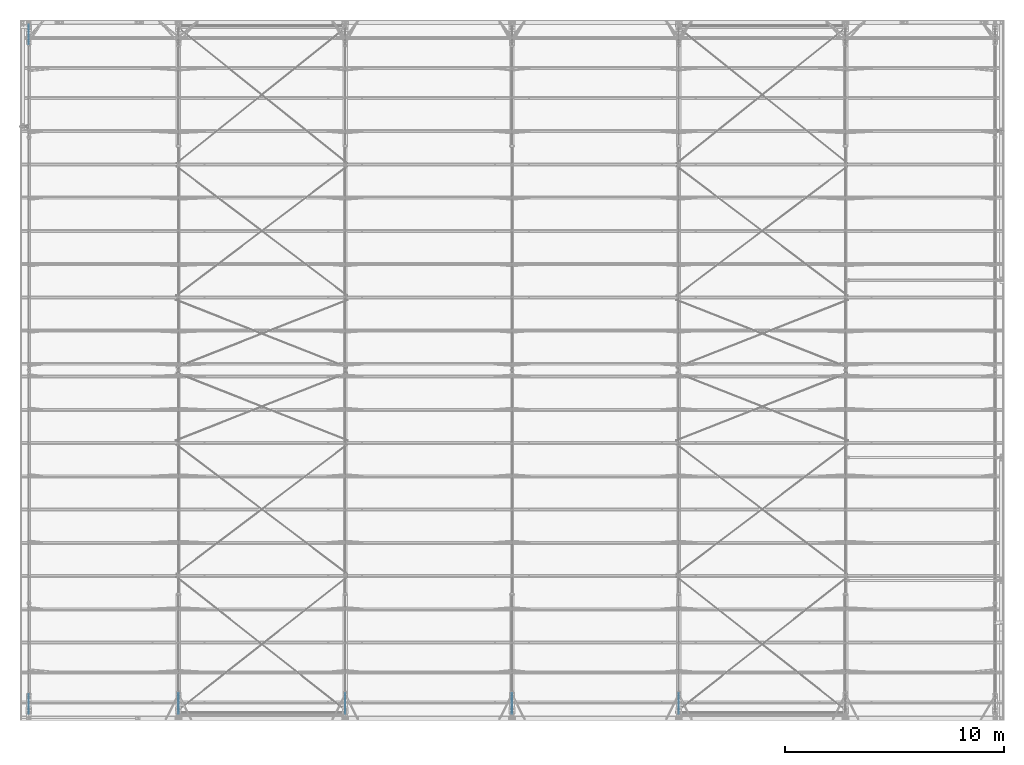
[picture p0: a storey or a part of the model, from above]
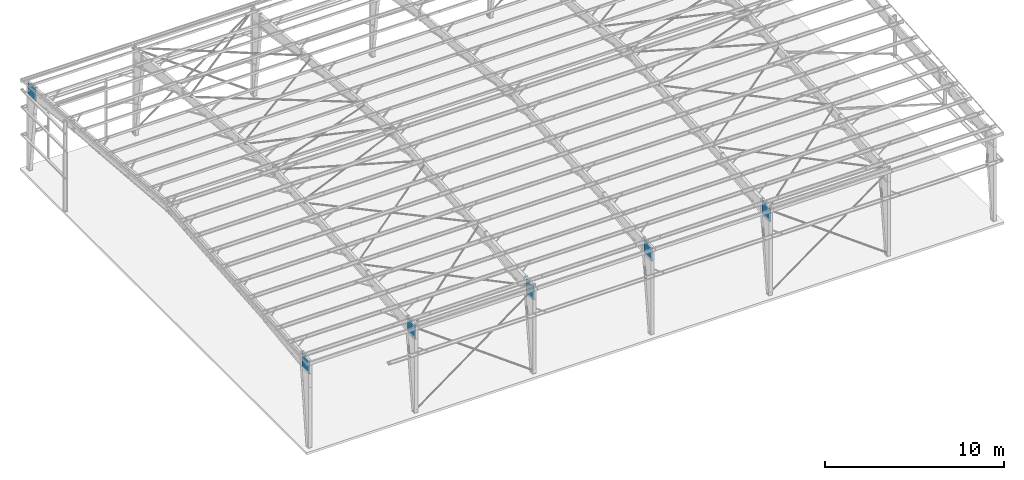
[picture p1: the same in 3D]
Properties of the parts of a building model (IFC2X3), part 1 of 2

# File
Description: ViewDefinition[CoordinationView_V1.0]
File name: IFC_Model.ifc
Time: 2022-11-29T19:15:44
Author: BG\Bryan.Morelli
Organization: Structural Designer
Written by: IFC Database Version:Work
Made in: Tekla Structures 2016i Service Pack 7, IFC Export Version: 4.0.0.0 Feb 5 2018

# IfcSite, Undefined
RefElevation: 0 mm

# IfcBuildingStorey, Undefined
In: Undefined
Elevation: 0 mm

# IfcBeam: 3/4_HEAVY_HEX_NUT (48)
In: Undefined
Description: 3/4_HEAVY_HEX_NUT; Material: STEEL/55
Tekla Common - Phase: 1; Class: 6
Tekla Quantity - Weight: 0.1 kg; Volume: 0 m3; Gross footprint area: 0 m2; Area per tons: 54.2 m2; Net surface area: 0 m2; Height: 31.6 mm; Width: 36.5 mm
Pset_BeamCommon - LoadBearing: yes; Reference: BH-80
Name | Bottom elevation | Top elevation | Length (mm)
5 x 3/4 H HEX NUT A563 | 20'-11"1/16 | 21'-0"3/8 | 19.1
6 x 3/4 H HEX NUT A563 | 20'-10"3/8 | 20'-11"11/16 | 19.1
7 x 3/4 H HEX NUT A563 | 22'-6"11/16 | 22'-7"15/16 | 19.1
7 x 3/4 H HEX NUT A563 | 23'-5"1/16 | 23'-6"5/16 | 19.1
3/4 H HEX NUT A563 | 22'-6"11/16 | 22'-7"15/16 | 19
3/4 H HEX NUT A563 | 23'-5"1/16 | 23'-6"5/16 | 19
5 x 3/4 H HEX NUT A563 | 22'-6"1/4 | 22'-7"1/2 | 19.1
3 x 3/4 H HEX NUT A563 | 22'-6"1/4 | 22'-7"1/2 | 19
3 x 3/4 H HEX NUT A563 | 20'-11"1/16 | 21'-0"3/8 | 19
4 x 3/4 H HEX NUT A563 | 19'-2"1/8 | 19'-3"3/8 | 19.1
2 x 3/4 H HEX NUT A563 | 20'-10"7/16 | 20'-11"11/16 | 19.1
4 x 3/4 H HEX NUT A563 | 19'-2"7/16 | 19'-3"11/16 | 19.1

# IfcBeam: 3/4_WASHER (48)
In: Undefined
Description: 3/4_WASHER; Material: STEEL/55
Tekla Common - Phase: 1; Class: 6
Tekla Quantity - Weight: 0 kg; Volume: 0 m3; Gross footprint area: 0 m2; Area per tons: 84.9 m2; Net surface area: 0 m2; Height: 36.4 mm; Width: 37.3 mm; Length: 4.8 mm
Pset_BeamCommon - LoadBearing: yes; Reference: BH-81
Name | Bottom elevation | Top elevation
8 x 3/4 WASHER F844 | 20'-11" | 21'-0"7/16
4 x 3/4 WASHER F844 | 20'-10"1/4 | 20'-11"3/4
4 x 3/4 WASHER F844 | 20'-10"5/16 | 20'-11"3/4
8 x 3/4 WASHER F844 | 22'-6"5/8 | 22'-8"1/16
8 x 3/4 WASHER F844 | 23'-4"15/16 | 23'-6"3/8
8 x 3/4 WASHER F844 | 22'-6"1/8 | 22'-7"9/16
4 x 3/4 WASHER F844 | 19'-2"1/16 | 19'-3"1/2
4 x 3/4 WASHER F844 | 19'-2"3/8 | 19'-3"13/16

# IfcBeam: 8C16 (4)
In: Undefined
Description: 8C16; Material: STEEL/55
Tekla Common - Finish: GZ; Phase: 1; Class: 12
Tekla Quantity - Volume: 0 m3; Area per tons: 171.1 m2; Height: 203.2 mm; Width: 63.5 mm
Pset_BeamCommon - LoadBearing: yes
Name | Bottom elevation | Top elevation | Weight (kg) | Gross footprint area (m2) | Net surface area (m2) | Length (mm) | Reference
2 x Jamb | 0" | 13'-4"1/2 | 17.4 | 0 | 2.9 | 4076.7 | C-12
2 x Header | 12'-0" | 12'-2"1/2 | 15.6 | 0.2 | 2.7 | 3657.6 | C-13

# IfcBeam: 8Z12 (6)
In: Undefined
Description: 8Z12; Material: STEEL/55
Tekla Common - Finish: GZ; Phase: 1; Class: 7
Tekla Quantity - Volume: 0 m3; Gross footprint area: 0 m2; Area per tons: 103.8 m2; Height: 203.2 mm; Width: 151.5 mm
Pset_BeamCommon - LoadBearing: yes
Name | Bottom elevation | Top elevation | Weight (kg) | Net surface area (m2) | Length (mm) | Reference
4 x Purlin | 19'-4"13/16 | 20'-1"3/16 | 54.9 | 5.7 | 7797.8 | Z-22
Girt | 13'-5" | 13'-11" | 57.1 | 6 | 8115.3 | Z-3
Girt | 13'-5" | 13'-11" | 57.1 | 6 | 8115.3 | Z-2

# IfcBeam: 8Z13 (46)
In: Undefined
Description: 8Z13; Material: STEEL/55
Tekla Common - Finish: GZ; Phase: 1; Class: 9
Tekla Quantity - Volume: 0 m3; Gross footprint area: 0 m2; Area per tons: 115.3 m2; Height: 203.2 mm; Width: 151.5 mm
Pset_BeamCommon - LoadBearing: yes
Name | Bottom elevation | Top elevation | Weight (kg) | Net surface area (m2) | Length (mm) | Reference
2 x Purlin | 19'-6"1/2 | 20'-2"7/8 | 53.5 | 6.2 | 8432.8 | Z-24
Purlin | 19'-11" | 20'-7"3/8 | 53.5 | 6.2 | 8432.8 | Z-28
2 x Purlin | 20'-3"7/16 | 20'-11"7/8 | 53.5 | 6.2 | 8432.8 | Z-24
2 x Purlin | 20'-8"7/16 | 21'-4"13/16 | 53.5 | 6.2 | 8432.8 | Z-24
2 x Purlin | 21'-1"7/16 | 21'-9"13/16 | 53.5 | 6.2 | 8432.8 | Z-24
2 x Purlin | 21'-6"7/16 | 22'-2"13/16 | 53.5 | 6.2 | 8432.8 | Z-24
2 x Purlin | 21'-11"3/8 | 22'-7"3/4 | 53.5 | 6.2 | 8432.8 | Z-24
2 x Purlin | 22'-4"3/8 | 23'-0"3/4 | 53.5 | 6.2 | 8432.8 | Z-24
2 x Purlin | 22'-9"3/8 | 23'-5"3/4 | 53.5 | 6.2 | 8432.8 | Z-24
2 x Purlin | 23'-2"5/16 | 23'-10"3/4 | 53.5 | 6.2 | 8432.8 | Z-24
2 x Purlin | 23'-7"5/16 | 24'-3"11/16 | 53.5 | 6.2 | 8432.8 | Z-24
2 x Purlin | 19'-6"1/2 | 20'-2"7/8 | 53.5 | 6.2 | 8432.8 | Z-23
Purlin | 19'-11" | 20'-7"3/8 | 53.5 | 6.2 | 8432.8 | Z-27
2 x Purlin | 20'-3"7/16 | 20'-11"7/8 | 53.5 | 6.2 | 8432.8 | Z-23
2 x Purlin | 20'-8"7/16 | 21'-4"13/16 | 53.5 | 6.2 | 8432.8 | Z-23
2 x Purlin | 21'-1"7/16 | 21'-9"13/16 | 53.5 | 6.2 | 8432.8 | Z-23
2 x Purlin | 21'-6"7/16 | 22'-2"13/16 | 53.5 | 6.2 | 8432.8 | Z-23
2 x Purlin | 21'-11"3/8 | 22'-7"3/4 | 53.5 | 6.2 | 8432.8 | Z-23
2 x Purlin | 22'-4"3/8 | 23'-0"3/4 | 53.5 | 6.2 | 8432.8 | Z-23
2 x Purlin | 22'-9"3/8 | 23'-5"3/4 | 53.5 | 6.2 | 8432.8 | Z-23
2 x Purlin | 23'-2"5/16 | 23'-10"3/4 | 53.5 | 6.2 | 8432.8 | Z-23
2 x Purlin | 23'-7"5/16 | 24'-3"11/16 | 53.5 | 6.2 | 8432.8 | Z-23
Purlin | 19'-11" | 20'-7"3/8 | 53.5 | 6.2 | 8432.8 | Z-26
Purlin | 19'-11" | 20'-7"3/8 | 53.5 | 6.2 | 8432.8 | Z-25
Girt | 13'-5" | 13'-11" | 42 | 4.9 | 6629.4 | Z-36
Girt | 13'-5" | 13'-11" | 39.9 | 4.6 | 6286.5 | Z-12

# IfcBeam: 8Z15 (96)
In: Undefined
Description: 8Z15; Material: STEEL/55
Tekla Common - Finish: GZ; Phase: 1; Class: 11
Tekla Quantity - Volume: 0 m3; Gross footprint area: 0 m2; Height: 203.2 mm; Width: 151.5 mm
Pset_BeamCommon - LoadBearing: yes
Name | Bottom elevation | Top elevation | Weight (kg) | Area per tons (m2) | Net surface area (m2) | Length (mm) | Reference
Girt | 7'-3" | 7'-9" | 22.7 | 151.6 | 3.4 | 4762.5 | Z-10
Girt | 7'-3" | 7'-9" | 23.6 | 151.7 | 3.6 | 4965.7 | Z-9
2 x Purlin | 19'-6"1/2 | 20'-2"7/8 | 45.8 | 153.5 | 7 | 9626.6 | Z-21
2 x Purlin | 19'-11" | 20'-7"3/8 | 45.8 | 153.5 | 7 | 9626.6 | Z-21
2 x Purlin | 20'-3"7/16 | 20'-11"7/8 | 45.8 | 153.5 | 7 | 9626.6 | Z-21
2 x Purlin | 20'-8"7/16 | 21'-4"13/16 | 45.8 | 153.5 | 7 | 9626.6 | Z-21
2 x Purlin | 21'-1"7/16 | 21'-9"13/16 | 45.8 | 153.5 | 7 | 9626.6 | Z-21
2 x Purlin | 21'-6"7/16 | 22'-2"13/16 | 45.8 | 153.5 | 7 | 9626.6 | Z-21
2 x Purlin | 21'-11"3/8 | 22'-7"3/4 | 45.8 | 153.5 | 7 | 9626.6 | Z-21
2 x Purlin | 22'-4"3/8 | 23'-0"3/4 | 45.8 | 153.5 | 7 | 9626.6 | Z-21
2 x Purlin | 22'-9"3/8 | 23'-5"3/4 | 45.8 | 153.5 | 7 | 9626.6 | Z-21
2 x Purlin | 23'-2"5/16 | 23'-10"3/4 | 45.8 | 153.5 | 7 | 9626.6 | Z-21
2 x Purlin | 23'-7"5/16 | 24'-3"11/16 | 45.8 | 153.5 | 7 | 9626.6 | Z-21
4 x Purlin | 19'-6"1/2 | 20'-2"7/8 | 43.9 | 153.5 | 6.7 | 9220.2 | Z-20
4 x Purlin | 19'-11" | 20'-7"3/8 | 43.9 | 153.5 | 6.7 | 9220.2 | Z-20
4 x Purlin | 20'-3"7/16 | 20'-11"7/8 | 43.9 | 153.5 | 6.7 | 9220.2 | Z-20
4 x Purlin | 20'-8"7/16 | 21'-4"13/16 | 43.9 | 153.5 | 6.7 | 9220.2 | Z-20
4 x Purlin | 21'-1"7/16 | 21'-9"13/16 | 43.9 | 153.5 | 6.7 | 9220.2 | Z-20
4 x Purlin | 21'-6"7/16 | 22'-2"13/16 | 43.9 | 153.5 | 6.7 | 9220.2 | Z-20
4 x Purlin | 21'-11"3/8 | 22'-7"3/4 | 43.9 | 153.5 | 6.7 | 9220.2 | Z-20
4 x Purlin | 22'-4"3/8 | 23'-0"3/4 | 43.9 | 153.5 | 6.7 | 9220.2 | Z-20
4 x Purlin | 22'-9"3/8 | 23'-5"3/4 | 43.9 | 153.5 | 6.7 | 9220.2 | Z-20
4 x Purlin | 23'-2"5/16 | 23'-10"3/4 | 43.9 | 153.5 | 6.7 | 9220.2 | Z-20
4 x Purlin | 23'-7"5/16 | 24'-3"11/16 | 43.9 | 153.5 | 6.7 | 9220.2 | Z-20
2 x Purlin | 19'-6"1/2 | 20'-2"7/8 | 45.8 | 153.5 | 7 | 9626.6 | Z-19
2 x Purlin | 19'-11" | 20'-7"3/8 | 45.8 | 153.5 | 7 | 9626.6 | Z-19
2 x Purlin | 20'-3"7/16 | 20'-11"7/8 | 45.8 | 153.5 | 7 | 9626.6 | Z-19
2 x Purlin | 20'-8"7/16 | 21'-4"13/16 | 45.8 | 153.5 | 7 | 9626.6 | Z-19
2 x Purlin | 21'-1"7/16 | 21'-9"13/16 | 45.8 | 153.5 | 7 | 9626.6 | Z-19
2 x Purlin | 21'-6"7/16 | 22'-2"13/16 | 45.8 | 153.5 | 7 | 9626.6 | Z-19
2 x Purlin | 21'-11"3/8 | 22'-7"3/4 | 45.8 | 153.5 | 7 | 9626.6 | Z-19
2 x Purlin | 22'-4"3/8 | 23'-0"3/4 | 45.8 | 153.5 | 7 | 9626.6 | Z-19
2 x Purlin | 22'-9"3/8 | 23'-5"3/4 | 45.8 | 153.5 | 7 | 9626.6 | Z-19
2 x Purlin | 23'-2"5/16 | 23'-10"3/4 | 45.8 | 153.5 | 7 | 9626.6 | Z-19
2 x Purlin | 23'-7"5/16 | 24'-3"11/16 | 45.8 | 153.5 | 7 | 9626.6 | Z-19
Girt | 17'-3" | 17'-9" | 22.7 | 153.5 | 3.4 | 4775.2 | Z-17
Girt | 13'-5" | 13'-11" | 22.7 | 151.6 | 3.4 | 4762.5 | Z-10
Girt | 13'-5" | 13'-11" | 23.6 | 151.7 | 3.6 | 4965.7 | Z-9
Girt | 13'-5" | 13'-11" | 25.9 | 153.5 | 4 | 5435.6 | Z-15
Girt | 13'-5" | 13'-11" | 43.4 | 153.5 | 6.7 | 9118.6 | Z-34
Girt | 13'-5" | 13'-11" | 43.4 | 153.5 | 6.7 | 9118.6 | Z-33

# IfcBeam: 8Z16 (19)
In: Undefined
Description: 8Z16; Material: STEEL/55
Tekla Common - Finish: GZ; Phase: 1; Class: 12
Tekla Quantity - Volume: 0 m3; Gross footprint area: 0 m2; Height: 203.2 mm; Width: 151.5 mm
Pset_BeamCommon - LoadBearing: yes
Name | Bottom elevation | Top elevation | Weight (kg) | Area per tons (m2) | Net surface area (m2) | Length (mm) | Reference
Girt | 7'-3" | 7'-9" | 7.2 | 171.4 | 1.2 | 1676.4 | Z-30
Girt | 7'-3" | 7'-9" | 14.9 | 171.1 | 2.5 | 3479.8 | Z-32
Girt | 19'-9" | 20'-3" | 28.3 | 171.1 | 4.9 | 6629.4 | Z-29
Girt | 19'-9" | 20'-3" | 23.2 | 171.1 | 4 | 5435.6 | Z-18
Girt | 19'-9" | 20'-3" | 9.5 | 171.4 | 1.6 | 2235.2 | Z-14
Girt | 13'-5" | 13'-11" | 33.4 | 171.1 | 5.7 | 7810.5 | Z-8
3 x Girt | 13'-5" | 13'-11" | 37.6 | 171.1 | 6.4 | 8813.8 | Z-31
Girt | 13'-5" | 13'-11" | 35 | 171.1 | 6 | 8204.2 | Z-7
Girt | 13'-5" | 13'-11" | 8.2 | 171.4 | 1.4 | 1930.4 | Z-6
Girt | 7'-3" | 7'-9" | 11.1 | 171.4 | 1.9 | 2603.5 | Z-5
Girt | 7'-3" | 7'-9" | 38.9 | 171.1 | 6.7 | 9118.6 | Z-16
2 x Girt | 13'-5" | 13'-11" | 37.6 | 171.1 | 6.4 | 8813.8 | Z-13
2 x Girt | 7'-3" | 7'-9" | 37.6 | 171.1 | 6.4 | 8813.8 | Z-13
Girt | 7'-3" | 7'-9" | 38.9 | 171.1 | 6.7 | 9118.6 | Z-1
Girt | 7'-3" | 7'-9" | 3.4 | 171.8 | 0.6 | 800.1 | Z-4

# IfcBeam: ESEIGHT1" (12)
In: Undefined
Description: ESEIGHT1"; Material: STEEL/55
Tekla Common - Finish: GZ; Bottom elevation: 19'-4"; Top elevation: 20'-0"5/16; Phase: 1; Class: 1
Tekla Quantity - Volume: 0 m3; Gross footprint area: 0 m2; Area per tons: 160.9 m2; Height: 212 mm; Width: 204.1 mm
Pset_BeamCommon - LoadBearing: yes
Name | Weight (kg) | Net surface area (m2) | Length (mm) | Reference
2 x Eave Strut | 55.4 | 8.9 | 7213.6 | GE8-2
8 x Eave Strut | 58.3 | 9.4 | 7594.6 | GE8-3
2 x Eave Strut | 55.4 | 8.9 | 7213.6 | GE8-1

# IfcBeam: FB- (35)
In: Undefined
Description: FB-; Material: STEEL/55
Tekla Common - Phase: 1; Class: 2
Tekla Quantity - Volume: 0 m3; Height: 50.8 mm; Width: 50.8 mm
Pset_BeamCommon - LoadBearing: yes
Name | Bottom elevation | Top elevation | Weight (kg) | Gross footprint area (m2) | Area per tons (m2) | Net surface area (m2) | Length (mm) | Reference
4 x 2X2 FLANGE BRACE X 48 | 7'-6" | 7'-8" | 1.4 | 0 | 163 | 0.2 | 1125.8 | FB-48
2 x 2X2 FLANGE BRACE X 36 | 7'-6"1/16 | 7'-8"1/16 | 1.2 | 0 | 163.1 | 0.2 | 934.6 | FB-36 | Tekla Common - Finish: RP
2X2 FLANGE BRACE X 60 | 13'-5"15/16 | 13'-7"15/16 | 1.4 | 0.1 | 163 | 0.2 | 1196.6 | FB-60 | Tekla Common - Finish: GZ
10 x 2X2 FLANGE BRACE X 60 | 13'-6" | 13'-8" | 1.4 | 0.1 | 163 | 0.2 | 1202.5 | FB-60 | Tekla Common - Finish: GZ
4 x 2X2 FLANGE BRACE X 60 | 13'-8" | 13'-10" | 1.6 | 0 | 163 | 0.3 | 1298.3 | FB-60
6 x 2X2 FLANGE BRACE X 48 | 7'-6" | 7'-8" | 1.1 | 0 | 163.1 | 0.2 | 912.7 | FB-48
6 x 2X2 FLANGE BRACE X 60 | 13'-8" | 13'-10" | 1.4 | 0 | 163 | 0.2 | 1120.2 | FB-60
2 x 2X2 FLANGE BRACE X 48 | 13'-8"1/16 | 13'-10"1/16 | 1.4 | 0 | 163 | 0.2 | 1115.7 | FB-48 | Tekla Common - Finish: RP

# IfcBeam: FL1/4"X5" (4)
In: Undefined
Description: FL1/4"X5"; Material: STEEL/55
Tekla Common - Finish: GP; Phase: 1; Class: 1
Tekla Quantity - Weight: 2.9 kg; Volume: 0 m3; Gross footprint area: 0 m2; Area per tons: 42.7 m2; Net surface area: 0.1 m2; Height: 127 mm; Width: 6.4 mm
Pset_BeamCommon - LoadBearing: yes; Reference: AC-151
Name | Bottom elevation | Top elevation | Length (mm)
Special Clip | 20'-0"5/8 | 20'-5"5/8 | 450.9
Special Clip | 20'-0"5/8 | 20'-5"5/8 | 450.8
Special Clip | 19'-11"15/16 | 20'-4"15/16 | 450.9
Special Clip | 19'-11"15/16 | 20'-4"15/16 | 450.8

# IfcBeam: FL1/4"X6" (22)
In: Undefined
Description: FL1/4"X6"; Material: STEEL/55
Tekla Common - Finish: GP; Phase: 1; Class: 2
Tekla Quantity - Volume: 0 m3; Gross footprint area: 0 m2; Net surface area: 0.1 m2; Height: 152.4 mm; Width: 6.4 mm
Pset_BeamCommon - LoadBearing: yes
Name | Bottom elevation | Top elevation | Weight (kg) | Area per tons (m2) | Length (mm) | Reference
12 x ANTI-ROLL CL 8 OR 9.5 | 23'-7"1/2 | 24'-3"1/4 | 2.5 | 42.6 | 323.8 | C-3
6 x 8 SECONDARY BYPASS | 13'-5" | 13'-8" | 2.7 | 42.5 | 342.9 | PX-100
2 x ANTI-ROLL CL 8 OR 9.5 | 23'-7"1/2 | 24'-3"1/4 | 2.5 | 42.6 | 323.8 | C-4
SPECIAL CLIP | 17'-6"1/16 | 17'-9"1/16 | 3.4 | 42.5 | 440.6 | AC-150
SPECIAL CLIP | 20'-0"1/16 | 20'-3"1/16 | 3.4 | 42.5 | 440.6 | AC-150

# IfcBeam: FL3/16"X5" (32)
In: Undefined
Description: FL3/16"X5"; Material: STEEL/55
Pset_BeamCommon - LoadBearing: yes; Reference: AC-01R
Tekla Common - Phase: 1; Class: 2
Tekla Quantity - Weight: 1.2 kg; Volume: 0 m3; Gross footprint area: 0 m2; Net surface area: 0.1 m2; Height: 127 mm; Width: 4.8 mm
Name | Finish | Bottom elevation | Top elevation | Area per tons (m2) | Length (mm)
5 x UNIVERSAL AC-1 CLIP | GZ | 7'-6" | 7'-8"3/4 | 56.5 | 244.5
UNIVERSAL AC-1 CLIP | GZ | 7'-6" | 7'-9" | 56.5 | 250.8
10 x UNIVERSAL AC-1 CLIP | GZ | 21'-1"5/8 | 21'-8"7/8 | 56.6 | 244.5
UNIVERSAL AC-1 CLIP | RP | 7'-6" | 7'-9" | 56.5 | 250.8
2 x UNIVERSAL AC-1 CLIP | GZ | 13'-8" | 13'-11" | 56.5 | 250.8
5 x UNIVERSAL AC-1 CLIP | GZ | 13'-8" | 13'-10"3/4 | 56.5 | 244.5
8 x UNIVERSAL AC-1 CLIP | GZ | 19'-5" | 20'-0"1/4 | 56.6 | 244.5

# IfcBeam: FLDPL2"X2"X1/16"X90" (7)
In: Undefined
Description: FLDPL2"X2"X1/16"X90"; Material: STEEL/55
Tekla Common - Finish: GZ; Phase: 1; Class: 9
Tekla Quantity - Weight: 0.3 kg; Volume: 0 m3; Gross footprint area: 0 m2; Area per tons: 164.3 m2; Net surface area: 0 m2; Height: 50.8 mm; Width: 50.8 mm; Length: 203.2 mm
Pset_BeamCommon - LoadBearing: yes; Reference: WA-8
Name | Bottom elevation | Top elevation
2 x WINDOW FRAME ANGLE | 7'-6"3/16 | 7'-8"3/16
3 x WINDOW FRAME ANGLE | 13'-8"3/16 | 13'-10"3/16
WINDOW FRAME ANGLE | 17'-6"3/16 | 17'-8"3/16
WINDOW FRAME ANGLE | 17'-6"1/16 | 17'-8"1/16

# IfcBeam: HSS4X4X1/4, PIPE
In: Undefined
Description: HSS4X4X1/4; Material: STEEL/55
Tekla Common - Finish: GP; Bottom elevation: 13'-10"11/16; Top elevation: 20'-10"3/16; Phase: 1; Class: 1
Tekla Quantity - Weight: 120.1 kg; Volume: 0 m3; Gross footprint area: 0 m2; Area per tons: 22.7 m2; Net surface area: 2.9 m2; Height: 101.6 mm; Width: 101.6 mm; Length: 7034.3 mm
Pset_BeamCommon - LoadBearing: yes; Reference: TF-2

# IfcBeam: PL1/4"X6" (10)
In: Undefined
Description: PL1/4"X6"; Material: STEEL/55
Tekla Common - Finish: GP; Bottom elevation: 19'-4"1/8; Top elevation: 19'-4"7/8; Phase: 1; Class: 1
Tekla Quantity - Weight: 2.3 kg; Volume: 0 m3; Gross footprint area: 0 m2; Area per tons: 42.6 m2; Net surface area: 0.1 m2; Height: 152.9 mm; Width: 6.4 mm; Length: 304.8 mm
Pset_BeamCommon - LoadBearing: yes; Reference: AC-13

# IfcBeam: PL1/8"X24" (10)
In: Undefined
Description: PL1/8"X24"; Material: STEEL/55
Tekla Common - Finish: GP; Bottom elevation: 18'-10"5/8; Top elevation: 22'-6"7/16; Phase: 1; Class: 8
Tekla Quantity - Weight: 99.7 kg; Volume: 0 m3; Gross footprint area: 0 m2; Area per tons: 75 m2; Net surface area: 7.5 m2; Height: 609.6 mm; Width: 3.4 mm; Length: 6096 mm
Pset_BeamCommon - LoadBearing: yes; Reference: WB-4

# IfcBeam: PL1/8"X28" (4)
In: Undefined
Description: PL1/8"X28"; Material: STEEL/55
Tekla Common - Finish: GP; Bottom elevation: 18'-5"3/8; Top elevation: 22'-5"3/16; Phase: 1; Class: 8
Tekla Quantity - Weight: 116.3 kg; Volume: 0 m3; Gross footprint area: 0 m2; Area per tons: 75 m2; Net surface area: 8.7 m2; Height: 711.2 mm; Width: 3.4 mm; Length: 6096 mm
Pset_BeamCommon - LoadBearing: yes
Name | Reference
3 x Web | WB-22
Web | WB-5

# IfcBeam: PL1/8"X5 7/8" (17)
In: Undefined
Description: PL1/8"X5 7/8"; Material: STEEL/55
Tekla Common - Finish: GZ; Phase: 1
Tekla Quantity - Weight: 0.9 kg; Volume: 0 m3; Gross footprint area: 0 m2; Area per tons: 82.9 m2; Net surface area: 0.1 m2; Height: 149.2 mm; Width: 3.2 mm; Length: 254 mm
Pset_BeamCommon - LoadBearing: yes; Reference: AC-01R
Name | Bottom elevation | Top elevation | Class
UNIVERSAL AC-1 CLIP | 13'-8"1/16 | 13'-11"1/16 | 2
4 x UNIVERSAL AC-1 CLIP | 0" | 7"1/4 | 1
4 x UNIVERSAL AC-1 CLIP | 13'-0"11/16 | 13'-7"15/16 | 2
4 x UNIVERSAL AC-1 CLIP | 12'-0"1/8 | 12'-3"1/8 | 2
4 x UNIVERSAL AC-1 CLIP | 7'-6"1/16 | 7'-9"1/16 | 2

# IfcBeam: PL3/16"X36" (14)
In: Undefined
Description: PL3/16"X36"; Material: STEEL/55
Tekla Common - Finish: GP; Phase: 1; Class: 8
Tekla Quantity - Volume: 0 m3; Gross footprint area: 0 m2; Area per tons: 53.9 m2; Width: 4.8 mm
Pset_BeamCommon - LoadBearing: yes
Name | Bottom elevation | Top elevation | Weight (kg) | Net surface area (m2) | Height (mm) | Length (mm) | Reference
2 x Web | 16'-7"5/16 | 20'-9"3/16 | 129.1 | 7 | 913.8 | 4291.1 | WB-19
2 x Web | 16'-7"5/8 | 20'-9"3/16 | 126 | 6.8 | 913.8 | 4189.2 | WB-18
5 x Web | 16'-7"7/16 | 20'-10"7/16 | 130.8 | 7 | 914.4 | 4635.5 | WB-7
5 x Web | 16'-7"3/4 | 20'-10"7/16 | 127.9 | 6.8 | 914.4 | 4533.6 | WB-6

# IfcBeam: RA-1 (20)
In: Undefined
Description: RA-1; Material: STEEL/55
Tekla Common - Finish: GZ; Phase: 1; Class: 5
Tekla Quantity - Volume: 0 m3; Gross footprint area: 0 m2; Area per tons: 169.1 m2; Height: 128.5 mm; Width: 52.3 mm
Pset_BeamCommon - LoadBearing: yes; Reference: RA-1
Name | Bottom elevation | Top elevation | Weight (kg) | Net surface area (m2) | Length (mm)
4 x STANDARD RAKE ANGLE | 23'-2"7/8 | 24'-4"9/16 | 5.7 | 1 | 2646.3
4 x STANDARD RAKE ANGLE | 22'-3"7/8 | 23'-7"7/8 | 7.2 | 1.2 | 3352.8
4 x STANDARD RAKE ANGLE | 21'-4"15/16 | 22'-8"15/16 | 7.2 | 1.2 | 3352.8
2 x STANDARD RAKE ANGLE | 20'-5"15/16 | 21'-9"15/16 | 7.2 | 1.2 | 3352.8
4 x STANDARD RAKE ANGLE | 19'-7" | 20'-11" | 7.2 | 1.2 | 3352.8
2 x STANDARD RAKE ANGLE | 20'-5"15/16 | 21'-10" | 7.2 | 1.2 | 3352.8

# IfcBeam: RB3/4" (24)
In: Undefined
Description: RB3/4"; Material: STEEL/55
Tekla Common - Phase: 1; Class: 14
Tekla Quantity - Volume: 0 m3; Gross footprint area: 0 m2; Area per tons: 29 m2; Height: 19.1 mm; Width: 19.1 mm
Pset_BeamCommon - LoadBearing: yes
Name | Bottom elevation | Top elevation | Weight (kg) | Net surface area (m2) | Length (mm) | Reference
8 x ROD BRACE - 3/4 | 22'-7"1/4 | 23'-6"1/8 | 16.9 | 0.5 | 8406.9 | r6_2
8 x ROD BRACE - 3/4 | 20'-11"1/4 | 22'-7"3/8 | 19.7 | 0.6 | 9778.9 | r6_1
4 x ROD BRACE - 3/4 | 19'-2"1/4 | 20'-11"1/2 | 20.1 | 0.6 | 9982.9 | r6-2
4 x ROD BRACE - 3/4 | 19'-2"5/8 | 20'-11"1/2 | 20 | 0.6 | 9931.9 | r6-1

# IfcColumn: 8C16 (2)
In: Undefined
Description: 8C16; Material: STEEL/55
Tekla Common - Finish: GZ; Bottom elevation: 0"; Top elevation: 13'-4"1/2; Phase: 1; Class: 12
Tekla Quantity - Weight: 17.4 kg; Volume: 0 m3; Gross footprint area: 0 m2; Area per tons: 171.1 m2; Net surface area: 2.9 m2; Height: 203.2 mm; Width: 63.5 mm; Length: 4076.7 mm
Pset_ColumnCommon - LoadBearing: yes; Reference: C-12

# IfcColumn: PL1/4"X35" (4)
In: Undefined
Description: PL1/4"X35"; Material: STEEL/55
Tekla Common - Finish: GP; Phase: 1; Class: 8
Tekla Quantity - Weight: 42.3 kg; Volume: 0 m3; Gross footprint area: 0 m2; Area per tons: 40.7 m2; Net surface area: 1.7 m2; Height: 889 mm; Width: 6.4 mm; Length: 991.2 mm
Pset_ColumnCommon - LoadBearing: yes
Name | Bottom elevation | Top elevation | Reference
2 x Web | 16'-4"5/8 | 19'-7"11/16 | WB-11
2 x Web | 16'-4"5/16 | 19'-7"5/16 | WB-10

# IfcColumn: PL5/16"X37" (10)
In: Undefined
Description: PL5/16"X37"; Material: STEEL/55
Tekla Common - Finish: GP; Phase: 1; Class: 8
Tekla Quantity - Weight: 56 kg; Volume: 0 m3; Gross footprint area: 0 m2; Area per tons: 32.6 m2; Net surface area: 1.7 m2; Height: 939.8 mm; Width: 7.9 mm; Length: 995.5 mm
Pset_ColumnCommon - LoadBearing: yes
Name | Bottom elevation | Top elevation | Reference
4 x Web | 16'-4"1/4 | 19'-7"7/16 | WB-3
4 x Web | 16'-4"9/16 | 19'-7"3/4 | WB-2
Web | 16'-4"1/4 | 19'-7"7/16 | WB-1
Web | 16'-4"9/16 | 19'-7"3/4 | WB-1

# IfcColumn: W8X10 (5)
In: Undefined
Description: W8X10; Material: STEEL/55
Tekla Common - Finish: GP; Phase: 1
Tekla Quantity - Volume: 0 m3; Gross footprint area: 0 m2; Height: 200 mm; Width: 101.6 mm
Pset_ColumnCommon - LoadBearing: yes
Name | Bottom elevation | Top elevation | Class | Weight (kg) | Area per tons (m2) | Net surface area (m2) | Length (mm) | Reference
COLUMN | 3/8 | 20'-5"5/8 | 8 | 93.4 | 52.8 | 4.9 | 6229.4 | WF-5
COLUMN | 3/8 | 20'-4"15/16 | 8 | 93.1 | 52.8 | 4.9 | 6211.9 | WF-6
COLUMN | 13'-0" | 20'-11"9/16 | 7 | 36.4 | 53.3 | 1.9 | 2427.3 | WF-1
COLUMN | 13'-0" | 22'-6" | 7 | 43.4 | 53.2 | 2.3 | 2895.6 | WF-4
COLUMN | 13'-0" | 22'-5"9/16 | 7 | 43.2 | 53.2 | 2.3 | 2884.5 | WF-2

# IfcCovering: GP (567)
In: Undefined
Material: Undefined/Undefined

# IfcCovering: GZ (411)
In: Undefined
Material: Undefined/Undefined

# IfcCovering: RP (5)
In: Undefined
Material: Undefined/Undefined

# IfcDiscreteAccessory: BACKUP PL SINGLE SLOT (8)
In: Undefined
Description: FL1/4"X4"; Material: STEEL/55
Tekla Common - Finish: GP; Phase: 1; Class: 8
Tekla Quantity - Weight: 0.9 kg; Volume: 0 m3; Gross footprint area: 0 m2; Area per tons: 44.1 m2; Net surface area: 0 m2; Height: 101.6 mm; Width: 6.4 mm; Length: 177.8 mm
Pset_PlateCommon - LoadBearing: yes; Reference: AC-25
Name | Bottom elevation | Top elevation
4 x BACKUP PL SINGLE SLOT | 3"1/8 | 10"1/8
4 x BACKUP PL SINGLE SLOT | 3"1/16 | 10"1/16

# IfcDiscreteAccessory: BEAM (3)
In: Undefined
Description: W8X10; Material: STEEL/55
Tekla Common - Finish: GP; Phase: 1; Class: 3
Tekla Quantity - Weight: 2.9 kg; Volume: 0 m3; Gross footprint area: 0 m2; Area per tons: 54.4 m2; Net surface area: 0.2 m2; Height: 200 mm; Width: 101.6 mm; Length: 195.1 mm
Pset_PlateCommon - LoadBearing: yes; Reference: WF-3
Name | Bottom elevation | Top elevation
BEAM | 20'-3"3/16 | 20'-11"1/16
BEAM | 21'-9"5/8 | 22'-5"1/2
BEAM | 21'-9"3/16 | 22'-5"1/16

# IfcDiscreteAccessory: Base Plate (16)
In: Undefined
Material: STEEL/55
Tekla Common - Finish: GP; Phase: 1; Class: 8
Tekla Quantity - Volume: 0 m3
Pset_PlateCommon - LoadBearing: yes
Name | Description | Bottom elevation | Top elevation | Weight (kg) | Gross footprint area (m2) | Area per tons (m2) | Net surface area (m2) | Height (mm) | Width (mm) | Length (mm) | Reference
2 x Base Plate | FL3/8"X8" | 0" | 3/8 | 3.1 | 0 | 29.3 | 0.1 | 203.2 | 9.5 | 203.2 | BP-3
7 x Base Plate | FL5/8"X10" | -0" | 5/8 | 9.6 | 0.1 | 17.9 | 0.2 | 254 | 15.9 | 304.9 | BP-1
2 x Base Plate | FL5/8"X10" | -0" | 5/8 | 10.5 | 0.1 | 17.8 | 0.2 | 254 | 15.9 | 330.3 | BP-2
5 x Base Plate | FL5/8"X10" | 0" | 5/8 | 10.5 | 0.1 | 17.8 | 0.2 | 254 | 15.9 | 330.3 | BP-2

# IfcDiscreteAccessory: Cap Plate (14)
In: Undefined
Material: STEEL/55
Tekla Common - Finish: GP; Phase: 1; Class: 8
Tekla Quantity - Volume: 0 m3; Gross footprint area: 0 m2; Net surface area: 0.5 m2; Height: 203.2 mm
Pset_PlateCommon - LoadBearing: yes
Name | Description | Bottom elevation | Top elevation | Weight (kg) | Area per tons (m2) | Width (mm) | Length (mm) | Reference
2 x Cap Plate | FL1/4"X8" | 19'-3"3/4 | 19'-7"15/16 | 12.2 | 41.6 | 6.4 | 1203.8 | EP-6
2 x Cap Plate | FL1/4"X8" | 19'-3"3/4 | 19'-7"9/16 | 11.1 | 41.6 | 6.4 | 1101.8 | EP-5
4 x Cap Plate | FL5/16"X8" | 19'-3"11/16 | 19'-7"3/4 | 14.6 | 33.5 | 7.9 | 1154.2 | EP-4
4 x Cap Plate | FL5/16"X8" | 19'-3"11/16 | 19'-8"1/16 | 15.9 | 33.5 | 7.9 | 1256.2 | EP-3
Cap Plate | FL5/16"X8" | 19'-3"11/16 | 19'-7"3/4 | 14.6 | 33.5 | 7.9 | 1154.2 | EP-2
Cap Plate | FL5/16"X8" | 19'-3"11/16 | 19'-8"1/16 | 15.9 | 33.5 | 7.9 | 1256.2 | EP-1

# IfcDiscreteAccessory: Column Connection Pla (14)
In: Undefined
Material: STEEL/55
Tekla Common - Finish: GP; Phase: 1; Class: 8
Tekla Quantity - Volume: 0 m3; Gross footprint area: 0 m2; Net surface area: 0.5 m2; Height: 203.2 mm
Pset_PlateCommon - LoadBearing: yes
Name | Description | Bottom elevation | Top elevation | Weight (kg) | Area per tons (m2) | Width (mm) | Length (mm) | Reference
2 x Column Connection Pla | FL1/2"X8" | 16'-4"5/8 | 19'-10"5/8 | 21.6 | 21.6 | 12.7 | 1066.8 | SP-7
2 x Column Connection Pla | FL1/2"X8" | 16'-4"5/16 | 19'-10"5/16 | 21.6 | 21.6 | 12.7 | 1066.8 | SP-7
5 x Column Connection Pla | FL5/8"X8" | 16'-4"1/4 | 19'-10"5/8 | 27.3 | 17.5 | 15.9 | 1076.3 | SP-1
5 x Column Connection Pla | FL5/8"X8" | 16'-4"9/16 | 19'-10"15/16 | 27.3 | 17.5 | 15.9 | 1076.3 | SP-1

# IfcDiscreteAccessory: End Splice Plate (14)
In: Undefined
Material: STEEL/55
Tekla Common - Finish: GP; Phase: 1; Class: 8
Tekla Quantity - Volume: 0 m3; Gross footprint area: 0 m2; Net surface area: 0.3 m2
Pset_PlateCommon - LoadBearing: yes
Name | Description | Bottom elevation | Top elevation | Weight (kg) | Area per tons (m2) | Height (mm) | Width (mm) | Length (mm) | Reference
2 x End Splice Plate | PL3/8"X6" | 18'-2"7/16 | 21'-0"1/16 | 9.8 | 28.4 | 152.4 | 9.7 | 857.3 | SP-11
2 x End Splice Plate | PL3/8"X6" | 18'-2"5/16 | 21'-0"3/16 | 10 | 28.4 | 152.4 | 9.7 | 863.6 | SP-10
10 x End Splice Plate | FL1/2"X8" | 18'-7"7/16 | 21'-1"5/8 | 15.6 | 21.6 | 203.2 | 12.7 | 768.3 | SP-5

# IfcDiscreteAccessory: FLANGE BRACE FLIP (210)
In: Undefined
Description: PL1/8"X2 3/4"; Material: STEEL/55
Tekla Common - Phase: 1; Class: 2
Tekla Quantity - Weight: 0.2 kg; Volume: 0 m3; Gross footprint area: 0 m2; Area per tons: 81.2 m2; Net surface area: 0 m2; Height: 69.9 mm; Width: 3.4 mm; Length: 85.7 mm
Pset_PlateCommon - LoadBearing: yes; Reference: FBC
Name | Bottom elevation | Top elevation | Finish
14 x FLANGE BRACE FLIP | 7'-5"7/8 | 7'-6"
4 x FLANGE BRACE FLIP | 13'-8" | 13'-8"1/8 | GP
10 x FLANGE BRACE FLIP | 13'-7"7/8 | 13'-8" | GP
14 x FLANGE BRACE FLIP | 13'-7"7/8 | 13'-8"
8 x FLANGE BRACE FLIP | 21'-3"3/8 | 21'-6"3/4 | GP
8 x FLANGE BRACE FLIP | 20'-10"3/8 | 21'-1"3/4 | GP
8 x FLANGE BRACE FLIP | 20'-0"7/16 | 20'-3"13/16 | GP
8 x FLANGE BRACE FLIP | 19'-2"7/16 | 19'-5"13/16 | GP
8 x FLANGE BRACE FLIP | 18'-4" | 18'-7"3/8 | GP
4 x FLANGE BRACE FLIP | 17'-1"1/16 | 17'-4"7/16 | GP
4 x FLANGE BRACE FLIP | 17'-1"3/16 | 17'-4"9/16 | GP
10 x FLANGE BRACE FLIP | 18'-6"11/16 | 18'-10"1/16 | GP
10 x FLANGE BRACE FLIP | 17'-1"5/8 | 17'-5" | GP
20 x FLANGE BRACE FLIP | 21'-7"5/16 | 21'-10"11/16 | GP
20 x FLANGE BRACE FLIP | 21'-2"5/16 | 21'-5"11/16 | GP
20 x FLANGE BRACE FLIP | 20'-4"5/16 | 20'-7"11/16 | GP
20 x FLANGE BRACE FLIP | 19'-6"3/8 | 19'-9"3/4 | GP
10 x FLANGE BRACE FLIP | 18'-6"3/4 | 18'-10"1/8 | GP
10 x FLANGE BRACE FLIP | 17'-1"13/16 | 17'-5"3/16 | GP

# IfcDiscreteAccessory: Gusett (6)
In: Undefined
Description: FL1/4"X2 3/4"; Material: STEEL/55
Tekla Common - Finish: GP; Bottom elevation: 13'-5"; Top elevation: 13'-7"3/4; Phase: 1; Class: 2
Tekla Quantity - Weight: 0.5 kg; Volume: 0 m3; Gross footprint area: 0 m2; Area per tons: 48.5 m2; Net surface area: 0 m2; Height: 69.8 mm; Width: 6.4 mm; Length: 273 mm
Pset_PlateCommon - LoadBearing: yes; Reference: PX-101

# IfcDiscreteAccessory: Gusset (14)
In: Undefined
Material: STEEL/55
Tekla Common - Finish: GP; Phase: 1; Class: 8
Tekla Quantity - Volume: 0 m3; Gross footprint area: 0 m2; Net surface area: 0 m2; Width: 6.4 mm
Pset_PlateCommon - LoadBearing: yes
Name | Description | Bottom elevation | Top elevation | Weight (kg) | Area per tons (m2) | Height (mm) | Length (mm) | Reference
2 x Gusset | 1/4"X2 15/16" | 19'-1"3/4 | 19'-4"3/4 | 0.6 | 47.7 | 75.2 | 308.4 | PX-5
5 x Gusset | 1/4"X2 15/16" | 19'-1"11/16 | 19'-4"11/16 | 0.6 | 47.7 | 75.2 | 308.4 | PX-5
5 x Gusset | 1/4"X2 7/8" | 19'-1"5/16 | 19'-4"5/16 | 0.3 | 48.2 | 73.1 | 211.2 | GP-1
2 x Gusset | 1/4"X2 7/8" | 19'-1"3/8 | 19'-4"3/8 | 0.3 | 48.2 | 73.1 | 211.2 | GP-1

# IfcDiscreteAccessory: Inside Flange (42)
In: Undefined
Material: STEEL/55
Tekla Common - Finish: GP; Phase: 1; Class: 8
Tekla Quantity - Volume: 0 m3; Gross footprint area: 0 m2
Pset_PlateCommon - LoadBearing: yes
Name | Description | Bottom elevation | Top elevation | Weight (kg) | Area per tons (m2) | Net surface area (m2) | Height (mm) | Width (mm) | Length (mm) | Reference
4 x Inside Flange | FL1/4"X5" | 18'-5"1/8 | 21'-4"1/16 | 67.3 | 42.2 | 2.8 | 127 | 6.4 | 10626.1 | IF-5
2 x Inside Flange | FL5/16"X6" | 16'-7" | 18'-5"1/4 | 40.5 | 34.1 | 1.4 | 152.4 | 7.9 | 4295.5 | IF-3
2 x Inside Flange | PL3/8"X6" | 16'-7"1/4 | 18'-5"1/4 | 48.4 | 28.1 | 1.4 | 152.4 | 9.7 | 4193.6 | IF-10
2 x Inside Flange | FL1/2"X8" | 5/8 | 16'-4"11/16 | 101.6 | 21.4 | 2.2 | 203.2 | 12.7 | 5014.1 | IF-2
2 x Inside Flange | FL1/2"X8" | 5/8 | 16'-4"5/16 | 101.4 | 21.4 | 2.2 | 203.2 | 12.7 | 5005.7 | IF-1
10 x Inside Flange | FL3/8"X6" | 18'-10"1/4 | 21'-8" | 116.5 | 28.4 | 3.3 | 152.4 | 9.5 | 10224.8 | IF-4
5 x Inside Flange | FL1/2"X8" | 16'-6"15/16 | 18'-10"1/2 | 94.1 | 21.4 | 1.9 | 203.2 | 12.7 | 4644.7 | IF-9
5 x Inside Flange | FL1/2"X8" | 16'-7"1/4 | 18'-10"1/2 | 92 | 21.4 | 1.9 | 203.2 | 12.7 | 4542.9 | IF-8
5 x Inside Flange | FL1/2"X8" | 5/8 | 16'-4"1/4 | 101.4 | 21.4 | 2.2 | 203.2 | 12.7 | 5010 | IF-7
5 x Inside Flange | FL1/2"X8" | 5/8 | 16'-4"9/16 | 101.6 | 21.4 | 2.2 | 203.2 | 12.7 | 5018.4 | IF-6

# IfcDiscreteAccessory: Outside Flange (42)
In: Undefined
Material: STEEL/55
Tekla Common - Finish: GP; Phase: 1; Class: 8
Tekla Quantity - Volume: 0 m3; Gross footprint area: 0 m2
Pset_PlateCommon - LoadBearing: yes
Name | Description | Bottom elevation | Top elevation | Weight (kg) | Area per tons (m2) | Net surface area (m2) | Height (mm) | Width (mm) | Length (mm) | Reference
4 x Outside Flange | FL1/4"X5" | 20'-9"1/4 | 23'-8"7/16 | 67.6 | 42.2 | 2.9 | 127 | 6.4 | 10685.9 | OF-10
2 x Outside Flange | FL1/4"X6" | 19'-7"7/16 | 20'-9"7/16 | 32 | 42 | 1.2 | 152.4 | 6.4 | 4214.5 | OF-9
2 x Outside Flange | FL5/16"X6" | 19'-7"3/4 | 20'-9"1/2 | 38.7 | 34.1 | 1.2 | 152.4 | 7.9 | 4112.4 | OF-6
2 x Outside Flange | FL1/4"X8" | 5/8 | 19'-4"3/4 | 59.7 | 41.4 | 2.5 | 203.2 | 6.4 | 5895.2 | OF-8
2 x Outside Flange | FL1/4"X8" | 5/8 | 19'-4"3/8 | 59.6 | 41.4 | 2.5 | 203.2 | 6.4 | 5886.8 | OF-7
10 x Outside Flange | FL5/16"X6" | 20'-10"1/2 | 23'-8"7/16 | 96.8 | 34.1 | 3.3 | 152.4 | 7.9 | 10276.4 | OF-3
5 x Outside Flange | FL5/16"X8" | 19'-7"9/16 | 20'-10"3/4 | 57.3 | 33.7 | 1.9 | 203.2 | 7.9 | 4558.7 | OF-5
5 x Outside Flange | FL5/16"X8" | 19'-7"7/8 | 20'-10"3/4 | 56 | 33.7 | 1.9 | 203.2 | 7.9 | 4456.7 | OF-4
5 x Outside Flange | FL5/16"X8" | 5/8 | 19'-4"5/16 | 73.9 | 33.7 | 2.5 | 203.2 | 7.9 | 5885.2 | OF-2
5 x Outside Flange | FL5/16"X8" | 5/8 | 19'-4"11/16 | 73.9 | 33.7 | 2.5 | 203.2 | 7.9 | 5893.6 | OF-1

# IfcDiscreteAccessory: PLATE (38)
In: Undefined
Material: STEEL/55
Tekla Common - Finish: GP; Phase: 1
Tekla Quantity - Volume: 0 m3; Gross footprint area: 0 m2
Pset_PlateCommon - LoadBearing: yes
Name | Description | Bottom elevation | Top elevation | Class | Weight (kg) | Area per tons (m2) | Net surface area (m2) | Height (mm) | Width (mm) | Length (mm) | Reference
2 x PLATE | FL1/4"X4" | 13'-8"15/16 | 14'-3" | 6 | 0.6 | 44.6 | 0 | 101.6 | 6.4 | 127 | PX-2
PLATE | FL1/4"X4" | 21'-11"7/8 | 22'-5"15/16 | 6 | 0.6 | 44.6 | 0 | 101.6 | 6.4 | 127 | PX-2
2 x PLATE | FL1/4"X5" | 13'-10"5/16 | 14'-3"1/16 | 6 | 0.9 | 44.1 | 0 | 127 | 6.4 | 127 | PX-4
PLATE | FL1/4"X5" | 21'-11"3/4 | 22'-4"9/16 | 6 | 0.9 | 44.1 | 0 | 127 | 6.4 | 127 | PX-4
PLATE | FL1/4"X4" | 22'-0"5/16 | 22'-6"3/8 | 6 | 0.6 | 44.6 | 0 | 101.6 | 6.4 | 127 | PX-2
PLATE | FL1/4"X5" | 22'-0"3/16 | 22'-5" | 6 | 0.9 | 44.1 | 0 | 127 | 6.4 | 127 | PX-4
PLATE | FL1/4"X4" | 13'-9" | 14'-2"15/16 | 6 | 0.6 | 44.6 | 0 | 101.6 | 6.4 | 127 | PX-2
PLATE | FL1/4"X4" | 20'-5"15/16 | 20'-11"7/8 | 6 | 0.6 | 44.6 | 0 | 101.6 | 6.4 | 127 | PX-2
PLATE | FL1/4"X5" | 13'-10"1/8 | 14'-3" | 6 | 0.9 | 44.1 | 0 | 127 | 6.4 | 127 | PX-4
PLATE | FL1/4"X5" | 20'-5"7/8 | 20'-10"11/16 | 6 | 0.9 | 44.1 | 0 | 127 | 6.4 | 127 | PX-4
PLATE | FL1/4"X4" | 22'-5"9/16 | 22'-5"13/16 | 5 | 0.9 | 43.9 | 0 | 101.6 | 6.4 | 200 | EP-7
PLATE | FL1/4"X4" | 22'-6" | 22'-6"1/4 | 5 | 0.9 | 43.9 | 0 | 101.6 | 6.4 | 200 | EP-7
PLATE | FL1/4"X4" | 20'-11"9/16 | 20'-11"13/16 | 5 | 0.9 | 43.9 | 0 | 101.6 | 6.4 | 200 | EP-7
14 x PLATE | FL1/4"X5 1/4" | 23'-7"13/16 | 24'-3"1/4 | 2 | 0.6 | 45.7 | 0 | 133.4 | 6.4 | 190.5 | G-1
PLATE | FL1/4"X5" | 22'-1"5/8 | 22'-6"5/8 | 6 | 0.9 | 44.1 | 0 | 127 | 6.4 | 127 | PX-3
PLATE | FL1/4"X5" | 22'-2"1/16 | 22'-7"1/16 | 6 | 0.9 | 44.1 | 0 | 127 | 6.4 | 127 | PX-3
PLATE | FL1/4"X5" | 20'-7"5/8 | 21'-0"5/8 | 6 | 0.9 | 44.1 | 0 | 127 | 6.4 | 127 | PX-3
2 x PLATE | FL1/4"X5" | 13'-8"1/4 | 14'-1"1/4 | 6 | 0.9 | 44.1 | 0 | 127 | 6.4 | 127 | PX-3
PLATE | FL1/4"X5" | 13'-8"3/16 | 14'-1"3/16 | 6 | 0.9 | 44.1 | 0 | 127 | 6.4 | 127 | PX-3
PLATE | FL3/8"X4" | 20'-2"11/16 | 20'-11"9/16 | 6 | 1.7 | 30.4 | 0.1 | 101.6 | 9.5 | 225.4 | PX-1
PLATE | FL3/8"X4" | 21'-9"1/8 | 22'-6" | 6 | 1.7 | 30.4 | 0.1 | 101.6 | 9.5 | 225.4 | PX-1
PLATE | FL3/8"X4" | 21'-8"11/16 | 22'-5"9/16 | 6 | 1.7 | 30.4 | 0.1 | 101.6 | 9.5 | 225.4 | PX-1

# IfcDiscreteAccessory: Rafter Haunch Plate (14)
In: Undefined
Material: STEEL/55
Tekla Common - Finish: GP; Phase: 1; Class: 8
Tekla Quantity - Volume: 0 m3; Gross footprint area: 0 m2
Pset_PlateCommon - LoadBearing: yes
Name | Description | Bottom elevation | Top elevation | Weight (kg) | Area per tons (m2) | Net surface area (m2) | Height (mm) | Width (mm) | Length (mm) | Reference
2 x Rafter Haunch Plate | FL1/2"X6" | 16'-4"5/16 | 19'-10"5/16 | 16.2 | 22 | 0.3 | 152.4 | 12.7 | 1066.8 | SP-8
2 x Rafter Haunch Plate | FL1/2"X6" | 16'-4"5/8 | 19'-10"5/8 | 16.2 | 22 | 0.3 | 152.4 | 12.7 | 1066.8 | SP-8
5 x Rafter Haunch Plate | PL5/8"X8" | 16'-4"1/4 | 19'-10"5/8 | 27 | 17.7 | 0.5 | 203.2 | 15.7 | 1076.3 | SP-12
5 x Rafter Haunch Plate | PL5/8"X8" | 16'-4"9/16 | 19'-10"15/16 | 27 | 17.7 | 0.5 | 203.2 | 15.7 | 1076.3 | SP-12

# IfcDiscreteAccessory: Rafter Ridge Plate (14)
In: Undefined
Material: STEEL/55
Tekla Common - Finish: GP; Phase: 1; Class: 8
Tekla Quantity - Volume: 0 m3; Gross footprint area: 0 m2; Net surface area: 0.3 m2; Height: 152.4 mm
Pset_PlateCommon - LoadBearing: yes
Name | Description | Bottom elevation | Top elevation | Weight (kg) | Area per tons (m2) | Width (mm) | Length (mm) | Reference
4 x Rafter Ridge Plate | FL3/8"X6" | 21'-1"1/4 | 23'-11"1/8 | 9.8 | 28.7 | 9.5 | 860.4 | SP-3
10 x Rafter Ridge Plate | FL1/2"X6" | 21'-5"1/8 | 23'-11"3/16 | 11.6 | 22.1 | 12.7 | 763.6 | SP-6

# IfcDiscreteAccessory: Start Splice Plate (14)
In: Undefined
Material: STEEL/55
Tekla Common - Finish: GP; Phase: 1; Class: 8
Tekla Quantity - Volume: 0 m3; Gross footprint area: 0 m2; Net surface area: 0.3 m2; Height: 152.4 mm
Pset_PlateCommon - LoadBearing: yes
Name | Description | Bottom elevation | Top elevation | Weight (kg) | Area per tons (m2) | Width (mm) | Length (mm) | Reference
2 x Start Splice Plate | FL3/8"X6" | 18'-2"7/16 | 21'-0"1/8 | 9.8 | 28.7 | 9.5 | 857.3 | SP-4
2 x Start Splice Plate | FL3/8"X6" | 18'-2"5/16 | 21'-0"1/4 | 9.8 | 28.7 | 9.5 | 863.6 | SP-2
10 x Start Splice Plate | PL3/8"X6" | 18'-7"7/16 | 21'-1"5/8 | 8.9 | 28.4 | 9.7 | 768.3 | SP-9

# IfcDiscreteAccessory: Stiff (34)
In: Undefined
Material: STEEL/55
Tekla Common - Finish: GP; Phase: 1; Class: 8
Tekla Quantity - Volume: 0 m3
Pset_PlateCommon - LoadBearing: yes
Name | Description | Bottom elevation | Top elevation | Weight (kg) | Gross footprint area (m2) | Area per tons (m2) | Net surface area (m2) | Height (mm) | Width (mm) | Length (mm) | Reference
Stiff | FL1/4"X2 1/2" | 20'-3"1/16 | 22'-7"1/8 | 2.3 | 0 | 44.5 | 0.1 | 63.5 | 6.4 | 712.8 | ST-3
Stiff | FL1/4"X2 1/2" | 20'-2"5/8 | 22'-6"11/16 | 2.3 | 0 | 44.5 | 0.1 | 63.5 | 6.4 | 712.8 | ST-3
Stiff | FL1/4"X2 1/2" | 18'-8"5/8 | 21'-0"11/16 | 2.3 | 0 | 44.5 | 0.1 | 63.5 | 6.4 | 712.8 | ST-3
3 x Stiff | FL1/4"X4" | 13'-8" | 13'-8"1/4 | 0.6 | 0 | 44.6 | 0 | 101.6 | 6.4 | 127 | ST-4
4 x Stiff | FL3/8"X4" | 16'-7"3/16 | 16'-7"9/16 | 6.8 | 0.1 | 29.5 | 0.2 | 101.6 | 9.5 | 889 | ST-2
4 x Stiff | FL3/8"X4" | 16'-6"7/8 | 16'-7"1/4 | 6.8 | 0.1 | 29.5 | 0.2 | 101.6 | 9.5 | 889 | ST-2
10 x Stiff | FL3/8"X4" | 16'-7" | 16'-7"3/8 | 7.2 | 0.1 | 29.5 | 0.2 | 101.6 | 9.5 | 939.8 | ST-1
10 x Stiff | FL3/8"X4" | 16'-7"5/16 | 16'-7"11/16 | 7.2 | 0.1 | 29.5 | 0.2 | 101.6 | 9.5 | 939.8 | ST-1

# IfcDiscreteAccessory: Web (28)
In: Undefined
Material: STEEL/55
Tekla Common - Finish: GP; Phase: 1; Class: 8
Tekla Quantity - Volume: 0 m3; Gross footprint area: 0 m2; Area per tons: 53.9 m2; Width: 4.8 mm
Pset_PlateCommon - LoadBearing: yes
Name | Description | Bottom elevation | Top elevation | Weight (kg) | Net surface area (m2) | Height (mm) | Length (mm) | Reference
Web | PL3/16"X28" | 20'-1"1/4 | 23'-8"3/16 | 121.2 | 6.4 | 711.2 | 4589.9 | WB-21
Web | PL3/16"X28" | 20'-1"1/4 | 23'-8"3/16 | 121.2 | 6.4 | 711.2 | 4589.9 | WB-20
2 x Web | PL3/16"X35" | 5/8 | 16'-4"5/8 | 109.3 | 6 | 889 | 4978.7 | WB-17
2 x Web | PL3/16"X35" | 5/8 | 16'-4"5/16 | 109.1 | 6 | 889 | 4970.2 | WB-16
2 x Web | PL3/16"X28" | 20'-1"1/4 | 23'-8"3/16 | 121.2 | 6.4 | 711.2 | 4589.9 | WB-9
10 x Web | PL3/16"X24" | 20'-6"9/16 | 23'-8"1/8 | 94.7 | 5.1 | 609.6 | 4180.4 | WB-8
4 x Web | PL3/16"X37" | 5/8 | 16'-4"1/4 | 113.7 | 6.2 | 939.8 | 4968.7 | WB-13
4 x Web | PL3/16"X37" | 5/8 | 16'-4"9/16 | 113.9 | 6.2 | 939.8 | 4977.1 | WB-12
Web | PL3/16"X37" | 5/8 | 16'-4"1/4 | 113.7 | 6.2 | 939.8 | 4968.7 | WB-15
Web | PL3/16"X37" | 5/8 | 16'-4"9/16 | 113.9 | 6.2 | 939.8 | 4977.1 | WB-14

# IfcDiscreteAccessory: XP-38 (24)
In: Undefined
Description: PL3/16"X5 7/8"; Material: STEEL/55
Tekla Common - Phase: 1; Class: 0
Tekla Quantity - Weight: 0.9 kg; Volume: 0 m3; Gross footprint area: 0 m2; Area per tons: 56.7 m2; Net surface area: 0.1 m2; Height: 149.2 mm; Width: 4.8 mm; Length: 168.3 mm
Pset_PlateCommon - LoadBearing: yes; Reference: XP-38
Name | Bottom elevation | Top elevation | Finish
4 x XP-38 | 7'-6" | 7'-6"3/16
4 x XP-38 | 13'-8" | 13'-8"3/16
2 x XP-38 | 17'-6" | 17'-6"3/16
8 x XP-38 | 20'-0" | 20'-0"3/16 | GP
6 x XP-38 | 13'-8" | 13'-8"3/16 | GP

# IfcElementAssembly (751)
In: Undefined
Name | PredefinedType | Assembly/Cast unit weight (kg) | Assembly/Cast unit bottom elevation | Assembly/Cast unit top elevation | Assembly/Cast unit position code | Assembly/Cast unit Mark
Steel Assembly | RIGID_FRAME | 3.4 | 7'-3" | 7'-9" | 6-7/A | ZW-6
Steel Assembly | RIGID_FRAME | 0.3 | 7'-6"3/16 | 7'-8"3/16 | 7/B-A | WA-8
Steel Assembly | RIGID_FRAME | 0.3 | 13'-8"3/16 | 13'-10"3/16 | 7/C-B | WA-8
Steel Assembly | RIGID_FRAME | 0.3 | 13'-8"3/16 | 13'-10"3/16 | 7/F-E | WA-8
Steel Assembly | RIGID_FRAME | 0.3 | 7'-6"3/16 | 7'-8"3/16 | 1/B-A | WA-8
Steel Assembly | RIGID_FRAME | 0.3 | 13'-8"3/16 | 13'-10"3/16 | 1/B-A | WA-8
Steel Assembly | RIGID_FRAME | 0.3 | 17'-6"3/16 | 17'-8"3/16 | 1/B-A | WA-8
Steel Assembly | RIGID_FRAME | 7.2 | 7'-3" | 7'-9" | 1-2/A | ZW-2
Steel Assembly | RIGID_FRAME | 101.8 | 0" | 20'-4"15/16 | 1/B-A | FC-10
Steel Assembly | RIGID_FRAME | 22.7 | 7'-3" | 7'-9" | 1/B-A | ZT-4
Steel Assembly | RIGID_FRAME | 0.3 | 17'-6"1/16 | 17'-8"1/16 | 1/A | WA-8
Steel Assembly | RIGID_FRAME | 397.9 | 18'-2"5/16 | 23'-11"1/8 | 7/G-E | FR-10
Steel Assembly | RIGID_FRAME | 53.5 | 19'-11" | 20'-7"3/8 | 5-7/B-A | ZX-6
Steel Assembly | RIGID_FRAME | 53.5 | 19'-11" | 20'-7"3/8 | 5-7/G-F | ZX-5
Steel Assembly | RIGID_FRAME | 53.5 | 19'-11" | 20'-7"3/8 | 1-3/B-A | ZX-4
Steel Assembly | RIGID_FRAME | 53.5 | 19'-11" | 20'-7"3/8 | 1-3/G-F | ZX-3
Steel Assembly | RIGID_FRAME | 102.1 | 0" | 20'-5"5/8 | 7/B-A | FC-11
Steel Assembly | RIGID_FRAME | 125.4 | 13'-8"15/16 | 22'-5"15/16 | 6-7/C-B | FT-1
Steel Assembly | RIGID_FRAME | 125.4 | 13'-8"15/16 | 22'-6"3/8 | 6-7/F-E | FT-3
Steel Assembly | RIGID_FRAME | 123 | 13'-9" | 20'-11"7/8 | 6-7/F | FT-2
Steel Assembly | RIGID_FRAME | 429.4 | 18'-7"7/16 | 23'-11"3/16 | 2/G-E | FR-9
Steel Assembly | RIGID_FRAME | 370.2 | -0" | 19'-10"5/16 | 7/B-A | FC-5
Steel Assembly | RIGID_FRAME | 370.8 | -0" | 19'-10"5/8 | 7/G-F | FC-4
Steel Assembly | RIGID_FRAME | 23.6 | 7'-3" | 7'-9" | 7/B-A | ZT-9
2 x Steel Assembly | RIGID_FRAME | 2.9 | 20'-0"5/8 | 20'-5"5/8 | 7/B-A | AC-151
2 x Steel Assembly | RIGID_FRAME | 2.9 | 19'-11"15/16 | 20'-4"15/16 | 1/B-A | AC-151
Steel Assembly | RIGID_FRAME | 1 | 13'-8"1/16 | 13'-11"1/16 | 1-2/G | AC-01R
2 x Steel Assembly | RIGID_FRAME | 1 | 0" | 7"1/4 | 6-7/A | AC-01R
2 x Steel Assembly | RIGID_FRAME | 17.4 | 0" | 13'-4"1/2 | 6-7/A | CW-1
2 x Steel Assembly | RIGID_FRAME | 1 | 0" | 7"1/4 | 1-2/A | AC-01R
2 x Steel Assembly | RIGID_FRAME | 17.4 | 0" | 13'-4"1/2 | 1-2/A | CW-1
2 x Steel Assembly | RIGID_FRAME | 1 | 13'-0"11/16 | 13'-7"15/16 | 1-2/A | AC-01R
2 x Steel Assembly | RIGID_FRAME | 1 | 12'-0"1/8 | 12'-3"1/8 | 1-2/A | AC-01R
2 x Steel Assembly | RIGID_FRAME | 1 | 7'-6"1/16 | 7'-9"1/16 | 1-2/A | AC-01R
2 x Steel Assembly | RIGID_FRAME | 1 | 7'-6"1/16 | 7'-9"1/16 | 6-7/A | AC-01R
2 x Steel Assembly | RIGID_FRAME | 1 | 12'-0"1/8 | 12'-3"1/8 | 6-7/A | AC-01R
2 x Steel Assembly | RIGID_FRAME | 1 | 13'-0"11/16 | 13'-7"15/16 | 6-7/A | AC-01R
Steel Assembly | RIGID_FRAME | 1.4 | 7'-6" | 7'-8" | 6-7/B-A | FB-48
Steel Assembly | RIGID_FRAME | 1.4 | 7'-6" | 7'-8" | 5-6/B-A | FB-48
Steel Assembly | RIGID_FRAME | 413.7 | 0" | 19'-10"5/8 | 6/B-A | FC-7
Steel Assembly | RIGID_FRAME | 38.9 | 7'-3" | 7'-9" | 4-7/A | ZW-5
Steel Assembly | RIGID_FRAME | 1.2 | 7'-6" | 7'-8"3/4 | 6/A | AC-01R
Steel Assembly | RIGID_FRAME | 370.2 | -0" | 19'-10"5/16 | 1/B-A | FC-5
Steel Assembly | RIGID_FRAME | 1.2 | 7'-6"1/16 | 7'-8"1/16 | 1-2/B-A | FB-36
Steel Assembly | RIGID_FRAME | 1.2 | 7'-6" | 7'-9" | 1/A | AC-01R
Steel Assembly | RIGID_FRAME | 15.6 | 12'-0" | 12'-2"1/2 | 1-2/A | CW-2
Steel Assembly | RIGID_FRAME | 14.9 | 7'-3" | 7'-9" | 5-7/A | ZW-11
Steel Assembly | RIGID_FRAME | 15.6 | 12'-0" | 12'-2"1/2 | 6-7/A | CW-2
Steel Assembly | RIGID_FRAME | 414.5 | -0" | 19'-10"15/16 | 6/G-F | FC-6
Steel Assembly | RIGID_FRAME | 414.5 | -0" | 19'-10"15/16 | 5/G-F | FC-6
Steel Assembly | RIGID_FRAME | 414.5 | -0" | 19'-10"15/16 | 3/G-F | FC-6
Steel Assembly | RIGID_FRAME | 413.7 | 0" | 19'-10"5/8 | 5/B-A | FC-7
Steel Assembly | RIGID_FRAME | 413.7 | 0" | 19'-10"5/8 | 3/B-A | FC-7
Steel Assembly | RIGID_FRAME | 429.4 | 18'-7"7/16 | 23'-11"3/16 | 4/G-E | FR-9
Steel Assembly | RIGID_FRAME | 429.4 | 18'-7"7/16 | 23'-11"3/16 | 4/C-A | FR-9
Steel Assembly | RIGID_FRAME | 1.7 | 19'-7"3/8 | 22'-2" | 1-2/F-E | FB-48
Steel Assembly | RIGID_FRAME | 1.2 | 19'-7"3/8 | 22'-2" | 2-3/F-E | FB-48
2 x Steel Assembly | RIGID_FRAME | 1.2 | 19'-7"3/8 | 22'-2" | 3-4/F-E | FB-48
2 x Steel Assembly | RIGID_FRAME | 1.2 | 19'-7"3/8 | 22'-2" | 4-5/F-E | FB-48
2 x Steel Assembly | RIGID_FRAME | 1.2 | 19'-7"3/8 | 22'-2" | 3-4/C-B | FB-48
2 x Steel Assembly | RIGID_FRAME | 1.2 | 19'-7"3/8 | 22'-2" | 4-5/C-B | FB-48
Steel Assembly | RIGID_FRAME | 1.2 | 19'-7"3/8 | 22'-2" | 5-6/C-B | FB-48
Steel Assembly | RIGID_FRAME | 1.7 | 19'-7"3/8 | 22'-2" | 2-3/C-B | FB-48
Steel Assembly | RIGID_FRAME | 1.7 | 19'-7"3/8 | 22'-2" | 6-7/C-B | FB-48
2 x Steel Assembly | RIGID_FRAME | 1.2 | 20'-5"5/16 | 23'-0" | 3-4/C-B | FB-48
2 x Steel Assembly | RIGID_FRAME | 1.2 | 20'-5"5/16 | 23'-0" | 4-5/C-B | FB-48
Steel Assembly | RIGID_FRAME | 1.2 | 20'-5"5/16 | 23'-0" | 5-6/C-B | FB-48
Steel Assembly | RIGID_FRAME | 1.7 | 20'-5"3/8 | 22'-11"15/16 | 2-3/C-B | FB-48
Steel Assembly | RIGID_FRAME | 1.7 | 20'-5"3/8 | 22'-11"15/16 | 6-7/C-B | FB-48
4 x Steel Assembly | RIGID_FRAME | 1.2 | 21'-3"1/4 | 23'-9"15/16 | 3-4/E-C | FB-48
4 x Steel Assembly | RIGID_FRAME | 1.2 | 21'-3"1/4 | 23'-9"15/16 | 4-5/E-C | FB-48
2 x Steel Assembly | RIGID_FRAME | 1.2 | 21'-3"1/4 | 23'-9"15/16 | 5-6/E-C | FB-48
2 x Steel Assembly | RIGID_FRAME | 1.7 | 21'-3"5/16 | 23'-9"7/8 | 2-3/E-C | FB-48
2 x Steel Assembly | RIGID_FRAME | 1.7 | 21'-3"5/16 | 23'-9"7/8 | 6-7/E-C | FB-48
4 x Steel Assembly | RIGID_FRAME | 1.2 | 21'-8"1/4 | 24'-2"15/16 | 3-4/E-C | FB-48
4 x Steel Assembly | RIGID_FRAME | 1.2 | 21'-8"1/4 | 24'-2"15/16 | 4-5/E-C | FB-48
2 x Steel Assembly | RIGID_FRAME | 1.2 | 21'-8"1/4 | 24'-2"15/16 | 5-6/E-C | FB-48
2 x Steel Assembly | RIGID_FRAME | 1.7 | 21'-8"5/16 | 24'-2"7/8 | 2-3/E-C | FB-48
2 x Steel Assembly | RIGID_FRAME | 1.7 | 21'-8"5/16 | 24'-2"7/8 | 6-7/E-C | FB-48
2 x Steel Assembly | RIGID_FRAME | 1.2 | 21'-8"1/4 | 24'-2"15/16 | 2-3/E-C | FB-48
2 x Steel Assembly | RIGID_FRAME | 1.7 | 21'-8"5/16 | 24'-2"7/8 | 1-2/E-C | FB-48
2 x Steel Assembly | RIGID_FRAME | 1.7 | 21'-8"5/16 | 24'-2"7/8 | 5-6/E-C | FB-48
2 x Steel Assembly | RIGID_FRAME | 1.2 | 21'-3"1/4 | 23'-9"15/16 | 2-3/E-C | FB-48
2 x Steel Assembly | RIGID_FRAME | 1.7 | 21'-3"5/16 | 23'-9"7/8 | 1-2/E-C | FB-48
2 x Steel Assembly | RIGID_FRAME | 1.7 | 21'-3"5/16 | 23'-9"7/8 | 5-6/E-C | FB-48
Steel Assembly | RIGID_FRAME | 1.2 | 20'-5"5/16 | 23'-0" | 2-3/F-E | FB-48
2 x Steel Assembly | RIGID_FRAME | 1.2 | 20'-5"5/16 | 23'-0" | 3-4/F-E | FB-48
2 x Steel Assembly | RIGID_FRAME | 1.2 | 20'-5"5/16 | 23'-0" | 4-5/F-E | FB-48
Steel Assembly | RIGID_FRAME | 1.7 | 20'-5"3/8 | 22'-11"15/16 | 1-2/F-E | FB-48
Steel Assembly | RIGID_FRAME | 1.7 | 20'-5"3/8 | 22'-11"15/16 | 5-6/F-E | FB-48
Steel Assembly | RIGID_FRAME | 1.7 | 19'-7"3/8 | 22'-2" | 5-6/F-E | FB-48
Steel Assembly | RIGID_FRAME | 1 | 5"3/16 | 8"3/16 | 3/G | BR-60
Steel Assembly | RIGID_FRAME | 0.1 | 4"5/16 | 6"1/4 | 3/G | BH-57
Steel Assembly | RIGID_FRAME | 0.1 | 4"11/16 | 6"7/16 | 3/G | BH-58
Steel Assembly | RIGID_FRAME | 1 | 5"3/16 | 8"3/16 | 5/G | BR-60
Steel Assembly | RIGID_FRAME | 0.1 | 4"5/16 | 6"1/4 | 5/G | BH-57
Steel Assembly | RIGID_FRAME | 0.1 | 4"11/16 | 6"7/16 | 5/G | BH-58
Steel Assembly | RIGID_FRAME | 1 | 5"3/16 | 8"3/16 | 6/G | BR-60
Steel Assembly | RIGID_FRAME | 0.1 | 4"5/16 | 6"1/4 | 6/G | BH-57
Steel Assembly | RIGID_FRAME | 0.1 | 4"11/16 | 6"7/16 | 6/G | BH-58
Steel Assembly | RIGID_FRAME | 429.4 | 18'-7"7/16 | 23'-11"3/16 | 5/G-E | FR-9
Steel Assembly | RIGID_FRAME | 1 | 20'-10"13/16 | 21'-0"13/16 | 5/F | BR-75
Steel Assembly | RIGID_FRAME | 0.1 | 20'-11"1/16 | 21'-0"3/8 | 5/F | BH-80
Steel Assembly | RIGID_FRAME | 0 | 20'-11" | 21'-0"7/16 | 5/F | BH-81
Steel Assembly | RIGID_FRAME | 429.4 | 18'-7"7/16 | 23'-11"3/16 | 2/C-A | FR-9
Steel Assembly | RIGID_FRAME | 1 | 20'-9"15/16 | 20'-11"15/16 | 2/B | BR-75
Steel Assembly | RIGID_FRAME | 0.1 | 20'-10"3/8 | 20'-11"11/16 | 2/B | BH-80
Steel Assembly | RIGID_FRAME | 0 | 20'-10"1/4 | 20'-11"3/4 | 2/B | BH-81
Steel Assembly | RIGID_FRAME | 1 | 20'-10"13/16 | 21'-0"13/16 | 2/B | BR-75
Steel Assembly | RIGID_FRAME | 0.1 | 20'-11"1/16 | 21'-0"3/8 | 2/B | BH-80
Steel Assembly | RIGID_FRAME | 0 | 20'-11" | 21'-0"7/16 | 2/B | BH-81
Steel Assembly | RIGID_FRAME | 1 | 20'-9"15/16 | 20'-11"7/8 | 2/F | BR-75
Steel Assembly | RIGID_FRAME | 0.1 | 20'-10"3/8 | 20'-11"11/16 | 2/F | BH-80
Steel Assembly | RIGID_FRAME | 0 | 20'-10"5/16 | 20'-11"3/4 | 2/F | BH-81
Steel Assembly | RIGID_FRAME | 1 | 20'-9"15/16 | 20'-11"7/8 | 5/F | BR-75
Steel Assembly | RIGID_FRAME | 0.1 | 20'-10"3/8 | 20'-11"11/16 | 5/F | BH-80
Steel Assembly | RIGID_FRAME | 0 | 20'-10"5/16 | 20'-11"3/4 | 5/F | BH-81
Steel Assembly | RIGID_FRAME | 54.1 | 13'-0" | 22'-5"13/16 | 7/C-B | FC-2
Steel Assembly | RIGID_FRAME | 395.5 | 18'-2"7/16 | 23'-11"1/8 | 7/C-A | FR-11
Steel Assembly | RIGID_FRAME | 54.3 | 13'-0" | 22'-6"1/4 | 7/F-E | FC-3
Steel Assembly | RIGID_FRAME | 47.2 | 13'-0" | 20'-11"13/16 | 7/F | FC-1
Steel Assembly | RIGID_FRAME | 45.8 | 23'-7"5/16 | 24'-3"11/16 | 1-4/E-C | ZT-1
2 x Steel Assembly | RIGID_FRAME | 3.1 | 23'-7"1/2 | 24'-3"1/4 | 2/E-C | AC-22
Steel Assembly | RIGID_FRAME | 9.5 | 17'-1"9/16 | 20'-6"3/4 | 1-2/G-F | FA-2
Steel Assembly | RIGID_FRAME | 9.5 | 17'-1"11/16 | 20'-6"3/4 | 1-2/B-A | FA-1
Steel Assembly | RIGID_FRAME | 9.5 | 17'-1"11/16 | 20'-6"3/4 | 6-7/B-A | FA-1
Steel Assembly | RIGID_FRAME | 9.5 | 17'-1"9/16 | 20'-6"3/4 | 6-7/G-F | FA-2
Steel Assembly | RIGID_FRAME | 1.2 | 21'-1"5/8 | 21'-8"7/8 | 2/B | AC-01R
Steel Assembly | RIGID_FRAME | 429.4 | 18'-7"7/16 | 23'-11"3/16 | 3/C-A | FR-9
Steel Assembly | RIGID_FRAME | 1.2 | 21'-1"5/8 | 21'-8"7/8 | 3/B | AC-01R
Steel Assembly | RIGID_FRAME | 1.2 | 21'-1"5/8 | 21'-8"7/8 | 4/B | AC-01R
Steel Assembly | RIGID_FRAME | 429.4 | 18'-7"7/16 | 23'-11"3/16 | 5/C-A | FR-9
Steel Assembly | RIGID_FRAME | 1.2 | 21'-1"5/8 | 21'-8"7/8 | 5/B | AC-01R
Steel Assembly | RIGID_FRAME | 430.2 | 18'-7"7/16 | 23'-11"3/16 | 6/C-A | FR-6
Steel Assembly | RIGID_FRAME | 1.2 | 21'-1"5/8 | 21'-8"7/8 | 6/B | AC-01R
Steel Assembly | RIGID_FRAME | 431 | 18'-7"7/16 | 23'-11"3/16 | 6/G-E | FR-7
Steel Assembly | RIGID_FRAME | 1.2 | 21'-1"5/8 | 21'-8"7/8 | 6/F | AC-01R
Steel Assembly | RIGID_FRAME | 1.2 | 21'-1"5/8 | 21'-8"7/8 | 5/F | AC-01R
Steel Assembly | RIGID_FRAME | 1.2 | 21'-1"5/8 | 21'-8"7/8 | 4/F | AC-01R
Steel Assembly | RIGID_FRAME | 429.4 | 18'-7"7/16 | 23'-11"3/16 | 3/G-E | FR-9
Steel Assembly | RIGID_FRAME | 1.2 | 21'-1"5/8 | 21'-8"7/8 | 3/F | AC-01R
Steel Assembly | RIGID_FRAME | 1.2 | 21'-1"5/8 | 21'-8"7/8 | 2/F | AC-01R
Steel Assembly | RIGID_FRAME | 39.9 | 13'-5" | 13'-11" | 7/G-F | ZX-7
Steel Assembly | RIGID_FRAME | 3.1 | 13'-5" | 13'-8" | 7/G | AC-250
Steel Assembly | RIGID_FRAME | 370.8 | -0" | 19'-10"5/8 | 1/G-F | FC-4
Steel Assembly | RIGID_FRAME | 3.1 | 13'-5" | 13'-8" | 6/G | AC-250
Steel Assembly | RIGID_FRAME | 3.1 | 13'-5" | 13'-8" | 5/G | AC-250
Steel Assembly | RIGID_FRAME | 3.1 | 13'-5" | 13'-8" | 4/G | AC-250
Steel Assembly | RIGID_FRAME | 3.1 | 13'-5" | 13'-8" | 3/G | AC-250
Steel Assembly | RIGID_FRAME | 3.1 | 13'-5" | 13'-8" | 2/G | AC-250
Steel Assembly | RIGID_FRAME | 1.4 | 13'-5"15/16 | 13'-7"15/16 | 6-7/G-F | FB-60
2 x Steel Assembly | RIGID_FRAME | 1.4 | 13'-6" | 13'-8" | 5-6/G-F | FB-60
Steel Assembly | RIGID_FRAME | 1.4 | 13'-6" | 13'-8" | 6-7/G-F | FB-60
Steel Assembly | RIGID_FRAME | 33.4 | 13'-5" | 13'-11" | 5-7/G | ZW-7
2 x Steel Assembly | RIGID_FRAME | 1.4 | 13'-6" | 13'-8" | 4-5/G-F | FB-60
Steel Assembly | RIGID_FRAME | 37.6 | 13'-5" | 13'-11" | 4-7/G | ZW-9
2 x Steel Assembly | RIGID_FRAME | 1.4 | 13'-6" | 13'-8" | 3-4/G-F | FB-60
Steel Assembly | RIGID_FRAME | 413.6 | -0" | 19'-10"15/16 | 4/G-F | FC-8
Steel Assembly | RIGID_FRAME | 37.6 | 13'-5" | 13'-11" | 3-6/G | ZW-9
2 x Steel Assembly | RIGID_FRAME | 1.4 | 13'-6" | 13'-8" | 2-3/G-F | FB-60
Steel Assembly | RIGID_FRAME | 37.6 | 13'-5" | 13'-11" | 2-5/G | ZW-9
Steel Assembly | RIGID_FRAME | 1.4 | 13'-6" | 13'-8" | 1-2/G-F | FB-60
Steel Assembly | RIGID_FRAME | 414.5 | -0" | 19'-10"15/16 | 2/G-F | FC-6
Steel Assembly | RIGID_FRAME | 53.5 | 20'-8"7/16 | 21'-4"13/16 | 1-3/G-F | ZX-1
Steel Assembly | RIGID_FRAME | 53.5 | 20'-3"7/16 | 20'-11"7/8 | 1-3/G-F | ZX-1
Steel Assembly | RIGID_FRAME | 45.8 | 21'-1"7/16 | 21'-9"13/16 | 1-4/F | ZT-1
Steel Assembly | RIGID_FRAME | 1.7 | 19'-7"3/8 | 22'-2" | 2-3/F-E | FB-48
Steel Assembly | RIGID_FRAME | 45.8 | 21'-6"7/16 | 22'-2"13/16 | 1-4/F-E | ZT-1
Steel Assembly | RIGID_FRAME | 45.8 | 21'-11"3/8 | 22'-7"3/4 | 1-4/F-E | ZT-1
Steel Assembly | RIGID_FRAME | 1.7 | 20'-5"3/8 | 22'-11"15/16 | 2-3/F-E | FB-48
Steel Assembly | RIGID_FRAME | 45.8 | 22'-4"3/8 | 23'-0"3/4 | 1-4/F-E | ZT-1
Steel Assembly | RIGID_FRAME | 45.8 | 22'-9"3/8 | 23'-5"3/4 | 1-4/E | ZT-1
Steel Assembly | RIGID_FRAME | 45.8 | 23'-2"5/16 | 23'-10"3/4 | 1-4/E-C | ZT-1
Steel Assembly | RIGID_FRAME | 45.8 | 21'-1"7/16 | 21'-9"13/16 | 4-7/F | ZT-2
Steel Assembly | RIGID_FRAME | 1.2 | 19'-7"3/8 | 22'-2" | 5-6/F-E | FB-48
Steel Assembly | RIGID_FRAME | 45.8 | 21'-6"7/16 | 22'-2"13/16 | 4-7/F-E | ZT-2
Steel Assembly | RIGID_FRAME | 45.8 | 21'-11"3/8 | 22'-7"3/4 | 4-7/F-E | ZT-2
Steel Assembly | RIGID_FRAME | 1.2 | 20'-5"5/16 | 23'-0" | 5-6/F-E | FB-48
Steel Assembly | RIGID_FRAME | 45.8 | 22'-4"3/8 | 23'-0"3/4 | 4-7/F-E | ZT-2
Steel Assembly | RIGID_FRAME | 45.8 | 22'-9"3/8 | 23'-5"3/4 | 4-7/E | ZT-2
Steel Assembly | RIGID_FRAME | 45.8 | 23'-2"5/16 | 23'-10"3/4 | 4-7/E-C | ZT-2
Steel Assembly | RIGID_FRAME | 45.8 | 23'-7"5/16 | 24'-3"11/16 | 4-7/E-C | ZT-2
2 x Steel Assembly | RIGID_FRAME | 3.1 | 23'-7"1/2 | 24'-3"1/4 | 5/E-C | AC-22
Steel Assembly | RIGID_FRAME | 53.5 | 23'-7"5/16 | 24'-3"11/16 | 1-3/E-C | ZX-2
Steel Assembly | RIGID_FRAME | 53.5 | 23'-2"5/16 | 23'-10"3/4 | 1-3/E-C | ZX-2
Steel Assembly | RIGID_FRAME | 53.5 | 22'-9"3/8 | 23'-5"3/4 | 1-3/C | ZX-2
Steel Assembly | RIGID_FRAME | 1.7 | 20'-5"3/8 | 22'-11"15/16 | 1-2/C-B | FB-48
Steel Assembly | RIGID_FRAME | 53.5 | 22'-4"3/8 | 23'-0"3/4 | 1-3/C-B | ZX-2
Steel Assembly | RIGID_FRAME | 53.5 | 21'-11"3/8 | 22'-7"3/4 | 1-3/C-B | ZX-2
Steel Assembly | RIGID_FRAME | 1.7 | 19'-7"3/8 | 22'-2" | 1-2/C-B | FB-48
Steel Assembly | RIGID_FRAME | 53.5 | 21'-6"7/16 | 22'-2"13/16 | 1-3/C-B | ZX-2
Steel Assembly | RIGID_FRAME | 53.5 | 21'-1"7/16 | 21'-9"13/16 | 1-3/B | ZX-2
Steel Assembly | RIGID_FRAME | 43.9 | 21'-1"7/16 | 21'-9"13/16 | 2-5/B | ZT-3
Steel Assembly | RIGID_FRAME | 43.9 | 21'-6"7/16 | 22'-2"13/16 | 2-5/C-B | ZT-3
2 x Steel Assembly | RIGID_FRAME | 43.9 | 23'-7"5/16 | 24'-3"11/16 | 2-5/E-C | ZT-3
2 x Steel Assembly | RIGID_FRAME | 3.1 | 23'-7"1/2 | 24'-3"1/4 | 4/E-C | AC-22
2 x Steel Assembly | RIGID_FRAME | 43.9 | 23'-2"5/16 | 23'-10"3/4 | 2-5/E-C | ZT-3
Steel Assembly | RIGID_FRAME | 43.9 | 22'-9"3/8 | 23'-5"3/4 | 2-5/C | ZT-3
Steel Assembly | RIGID_FRAME | 43.9 | 21'-11"3/8 | 22'-7"3/4 | 2-5/C-B | ZT-3
Steel Assembly | RIGID_FRAME | 43.9 | 22'-4"3/8 | 23'-0"3/4 | 2-5/C-B | ZT-3
Steel Assembly | RIGID_FRAME | 412.8 | 0" | 19'-10"5/8 | 4/B-A | FC-9
Steel Assembly | RIGID_FRAME | 413.7 | 0" | 19'-10"5/8 | 2/B-A | FC-7
Steel Assembly | RIGID_FRAME | 228.3 | 16'-4"5/16 | 21'-0"1/16 | 1/B-A | FR-4
Steel Assembly | RIGID_FRAME | 228.3 | 16'-4"5/16 | 21'-0"1/16 | 7/B-A | FR-4
Steel Assembly | RIGID_FRAME | 240 | 16'-4"5/8 | 21'-0"3/16 | 7/G-F | FR-1
Steel Assembly | RIGID_FRAME | 240 | 16'-4"5/8 | 21'-0"3/16 | 1/G-F | FR-1
Steel Assembly | RIGID_FRAME | 393.4 | 18'-2"5/16 | 23'-11"1/8 | 1/G-E | FR-2
Steel Assembly | RIGID_FRAME | 1.6 | 13'-8" | 13'-10" | 6-7/B-A | FB-60
Steel Assembly | RIGID_FRAME | 1.6 | 13'-8" | 13'-10" | 5-6/B-A | FB-60
Steel Assembly | RIGID_FRAME | 1.1 | 7'-6" | 7'-8" | 5-6/B-A | FB-48
2 x Steel Assembly | RIGID_FRAME | 1.1 | 7'-6" | 7'-8" | 4-5/B-A | FB-48
Steel Assembly | RIGID_FRAME | 1.4 | 13'-8" | 13'-10" | 5-6/B-A | FB-60
2 x Steel Assembly | RIGID_FRAME | 1.4 | 13'-8" | 13'-10" | 4-5/B-A | FB-60
2 x Steel Assembly | RIGID_FRAME | 1.4 | 13'-8" | 13'-10" | 3-4/B-A | FB-60
2 x Steel Assembly | RIGID_FRAME | 1.1 | 7'-6" | 7'-8" | 3-4/B-A | FB-48
Steel Assembly | RIGID_FRAME | 1.4 | 13'-8" | 13'-10" | 2-3/B-A | FB-60
Steel Assembly | RIGID_FRAME | 1.1 | 7'-6" | 7'-8" | 2-3/B-A | FB-48
Steel Assembly | RIGID_FRAME | 1.4 | 7'-6" | 7'-8" | 2-3/B-A | FB-48
Steel Assembly | RIGID_FRAME | 1.4 | 7'-6" | 7'-8" | 1-2/B-A | FB-48
Steel Assembly | RIGID_FRAME | 1.6 | 13'-8" | 13'-10" | 2-3/B-A | FB-60
Steel Assembly | RIGID_FRAME | 1.6 | 13'-8" | 13'-10" | 1-2/B-A | FB-60
Steel Assembly | RIGID_FRAME | 1.4 | 13'-8"1/16 | 13'-10"1/16 | 6-7/B-A | FB-48
Steel Assembly | RIGID_FRAME | 1.2 | 7'-6"1/16 | 7'-8"1/16 | 6-7/B-A | FB-36
Steel Assembly | RIGID_FRAME | 1.4 | 13'-8"1/16 | 13'-10"1/16 | 1-2/B-A | FB-48
2 x Steel Assembly | RIGID_FRAME | 5.7 | 23'-2"7/8 | 24'-4"9/16 | 1/E-C | RA-1
Steel Assembly | RIGID_FRAME | 7.2 | 22'-3"7/8 | 23'-7"7/8 | 1/E-B | RA-1
Steel Assembly | RIGID_FRAME | 7.2 | 21'-4"15/16 | 22'-8"15/16 | 1/C-B | RA-1
Steel Assembly | RIGID_FRAME | 7.2 | 20'-5"15/16 | 21'-9"15/16 | 1/B-A | RA-1
Steel Assembly | RIGID_FRAME | 7.2 | 19'-7" | 20'-11" | 1/B-A | RA-1
2 x Steel Assembly | RIGID_FRAME | 5.7 | 23'-2"7/8 | 24'-4"9/16 | 7/E-C | RA-1
Steel Assembly | RIGID_FRAME | 7.2 | 22'-3"7/8 | 23'-7"7/8 | 7/E-B | RA-1
Steel Assembly | RIGID_FRAME | 7.2 | 21'-4"15/16 | 22'-8"15/16 | 7/C-B | RA-1
Steel Assembly | RIGID_FRAME | 7.2 | 20'-5"15/16 | 21'-10" | 7/B-A | RA-1
Steel Assembly | RIGID_FRAME | 7.2 | 19'-7" | 20'-11" | 7/B-A | RA-1
Steel Assembly | RIGID_FRAME | 7.2 | 22'-3"7/8 | 23'-7"7/8 | 7/F-C | RA-1
Steel Assembly | RIGID_FRAME | 7.2 | 21'-4"15/16 | 22'-8"15/16 | 7/F-E | RA-1
Steel Assembly | RIGID_FRAME | 7.2 | 20'-5"15/16 | 21'-9"15/16 | 7/G-F | RA-1
Steel Assembly | RIGID_FRAME | 7.2 | 19'-7" | 20'-11" | 7/G-F | RA-1
Steel Assembly | RIGID_FRAME | 7.2 | 22'-3"7/8 | 23'-7"7/8 | 1/F-C | RA-1
Steel Assembly | RIGID_FRAME | 7.2 | 21'-4"15/16 | 22'-8"15/16 | 1/F-E | RA-1
Steel Assembly | RIGID_FRAME | 7.2 | 20'-5"15/16 | 21'-10" | 1/G-F | RA-1
Steel Assembly | RIGID_FRAME | 7.2 | 19'-7" | 20'-11" | 1/G-F | RA-1
2 x Steel Assembly | RIGID_FRAME | 3.1 | 23'-7"1/2 | 24'-3"1/4 | 7/E-C | AC-22
2 x Steel Assembly | RIGID_FRAME | 3.1 | 23'-7"1/2 | 24'-3"1/4 | 1/E-C | AC-22
2 x Steel Assembly | RIGID_FRAME | 1.2 | 21'-4"3/8 | 24'-2"7/8 | 1-2/E-C | FB-48
2 x Steel Assembly | RIGID_FRAME | 1.2 | 21'-4"3/8 | 24'-2"7/8 | 6-7/E-C | FB-48
2 x Steel Assembly | RIGID_FRAME | 1.2 | 20'-11"3/8 | 23'-9"15/16 | 1-2/E-C | FB-48
2 x Steel Assembly | RIGID_FRAME | 1.2 | 20'-11"3/8 | 23'-9"15/16 | 6-7/E-C | FB-48
Steel Assembly | RIGID_FRAME | 1.2 | 20'-1"7/16 | 22'-11"15/16 | 1-2/F-E | FB-48
Steel Assembly | RIGID_FRAME | 1.2 | 20'-1"7/16 | 22'-11"15/16 | 6-7/F-E | FB-48
Steel Assembly | RIGID_FRAME | 1.2 | 19'-3"7/16 | 22'-2" | 1-2/F-E | FB-48
Steel Assembly | RIGID_FRAME | 1.2 | 19'-3"7/16 | 22'-2" | 6-7/F-E | FB-48
Steel Assembly | RIGID_FRAME | 1.2 | 18'-5" | 21'-4" | 1-2/G-F | FB-48
Steel Assembly | RIGID_FRAME | 1.2 | 18'-5" | 21'-4" | 6-7/G-F | FB-48
Steel Assembly | RIGID_FRAME | 393.3 | 18'-2"7/16 | 23'-11"1/8 | 1/C-A | FR-3
Steel Assembly | RIGID_FRAME | 1.2 | 20'-1"7/16 | 22'-11"15/16 | 6-7/C-B | FB-48
Steel Assembly | RIGID_FRAME | 1.2 | 20'-1"7/16 | 22'-11"15/16 | 1-2/C-B | FB-48
Steel Assembly | RIGID_FRAME | 1.2 | 19'-3"7/16 | 22'-2" | 6-7/C-B | FB-48
Steel Assembly | RIGID_FRAME | 1.2 | 19'-3"7/16 | 22'-2" | 1-2/C-B | FB-48
Steel Assembly | RIGID_FRAME | 1.2 | 18'-5" | 21'-4" | 6-7/B-A | FB-48
Steel Assembly | RIGID_FRAME | 1.2 | 18'-5" | 21'-4" | 1-2/B-A | FB-48
2 x Steel Assembly | RIGID_FRAME | 3.1 | 23'-7"1/2 | 24'-3"1/4 | 3/E-C | AC-22
2 x Steel Assembly | RIGID_FRAME | 3.1 | 23'-7"1/2 | 24'-3"1/4 | 6/E-C | AC-22
Steel Assembly | RIGID_FRAME | 1.4 | 18'-7"5/8 | 21'-4"1/16 | 2-3/G-F | FB-48
2 x Steel Assembly | RIGID_FRAME | 1.4 | 18'-7"5/8 | 21'-4"1/16 | 3-4/G-F | FB-48
Steel Assembly | RIGID_FRAME | 319.2 | 16'-4"9/16 | 21'-1"5/8 | 3/G-F | FR-5
2 x Steel Assembly | RIGID_FRAME | 1.4 | 18'-7"5/8 | 21'-4"1/16 | 4-5/G-F | FB-48
Steel Assembly | RIGID_FRAME | 319.2 | 16'-4"9/16 | 21'-1"5/8 | 4/G-F | FR-5
Steel Assembly | RIGID_FRAME | 1.4 | 18'-7"5/8 | 21'-4"1/16 | 5-6/G-F | FB-48
Steel Assembly | RIGID_FRAME | 319.2 | 16'-4"9/16 | 21'-1"5/8 | 5/G-F | FR-5
Steel Assembly | RIGID_FRAME | 1.7 | 18'-7"11/16 | 21'-4" | 1-2/G-F | FB-48
Steel Assembly | RIGID_FRAME | 1.7 | 18'-7"11/16 | 21'-4" | 2-3/G-F | FB-48
Steel Assembly | RIGID_FRAME | 319.2 | 16'-4"9/16 | 21'-1"5/8 | 2/G-F | FR-5
Steel Assembly | RIGID_FRAME | 1.7 | 18'-7"11/16 | 21'-4" | 5-6/G-F | FB-48
Steel Assembly | RIGID_FRAME | 1.7 | 18'-7"11/16 | 21'-4" | 6-7/G-F | FB-48
Steel Assembly | RIGID_FRAME | 319.2 | 16'-4"9/16 | 21'-1"5/8 | 6/G-F | FR-5
Steel Assembly | RIGID_FRAME | 1.6 | 17'-2"9/16 | 20'-6"9/16 | 2-3/G-F | FB-60
2 x Steel Assembly | RIGID_FRAME | 1.6 | 17'-2"9/16 | 20'-6"9/16 | 3-4/G-F | FB-60
2 x Steel Assembly | RIGID_FRAME | 1.6 | 17'-2"9/16 | 20'-6"9/16 | 4-5/G-F | FB-60
Steel Assembly | RIGID_FRAME | 1.6 | 17'-2"9/16 | 20'-6"9/16 | 5-6/G-F | FB-60
Steel Assembly | RIGID_FRAME | 1.9 | 17'-2"9/16 | 20'-6"9/16 | 1-2/G-F | FB-60
Steel Assembly | RIGID_FRAME | 1.9 | 17'-2"9/16 | 20'-6"9/16 | 2-3/G-F | FB-60
Steel Assembly | RIGID_FRAME | 1.9 | 17'-2"9/16 | 20'-6"9/16 | 5-6/G-F | FB-60
Steel Assembly | RIGID_FRAME | 1.9 | 17'-2"9/16 | 20'-6"9/16 | 6-7/G-F | FB-60
Steel Assembly | RIGID_FRAME | 1.7 | 20'-5"3/8 | 22'-11"15/16 | 6-7/F-E | FB-48
Steel Assembly | RIGID_FRAME | 1.7 | 19'-7"3/8 | 22'-2" | 6-7/F-E | FB-48
2 x Steel Assembly | RIGID_FRAME | 1.4 | 18'-7"11/16 | 21'-4"1/16 | 3-4/B-A | FB-48
Steel Assembly | RIGID_FRAME | 1.4 | 18'-7"11/16 | 21'-4"1/16 | 2-3/B-A | FB-48
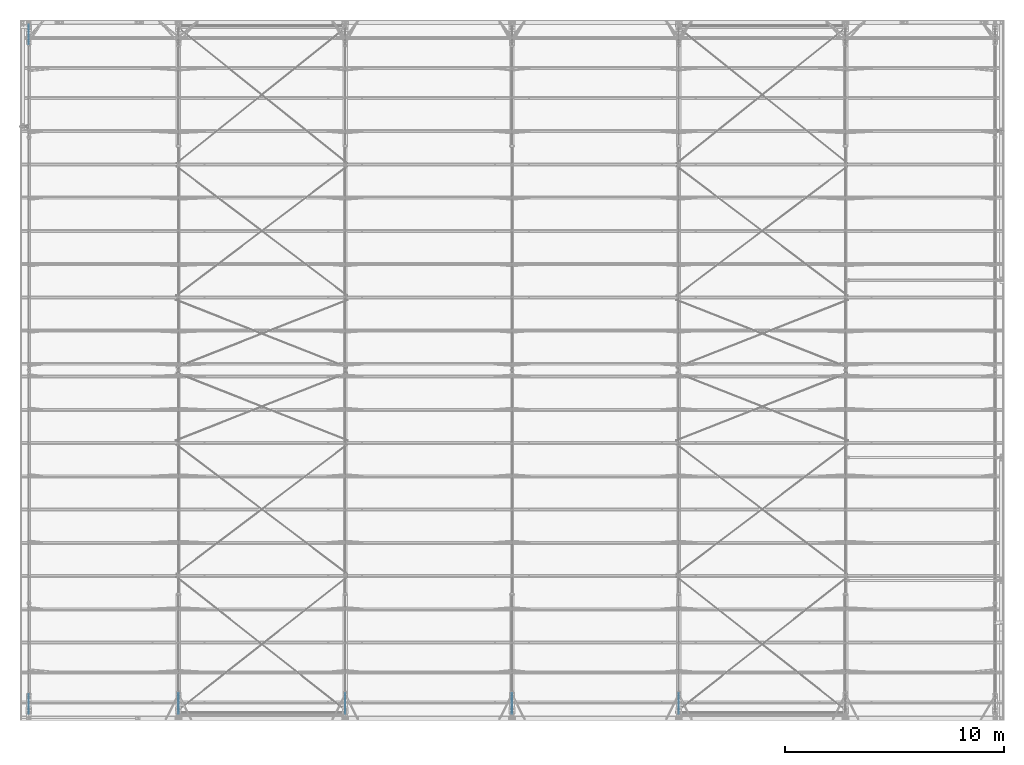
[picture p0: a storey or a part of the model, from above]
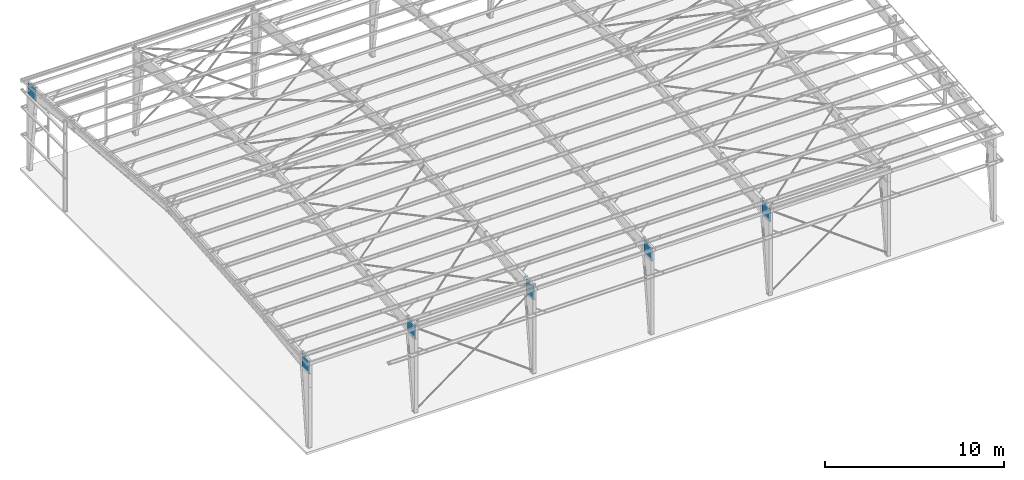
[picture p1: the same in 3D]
Properties of the parts of a building model (IFC2X3), part 2 of 2

# IfcElementAssembly (751)
Name | PredefinedType | Assembly/Cast unit weight (kg) | Assembly/Cast unit bottom elevation | Assembly/Cast unit top elevation | Assembly/Cast unit position code | Assembly/Cast unit Mark
Steel Assembly | RIGID_FRAME | 325.4 | 16'-4"1/4 | 21'-1"5/8 | 3/B-A | FR-8
2 x Steel Assembly | RIGID_FRAME | 1.4 | 18'-7"11/16 | 21'-4"1/16 | 4-5/B-A | FB-48
Steel Assembly | RIGID_FRAME | 325.4 | 16'-4"1/4 | 21'-1"5/8 | 4/B-A | FR-8
Steel Assembly | RIGID_FRAME | 1.4 | 18'-7"11/16 | 21'-4"1/16 | 5-6/B-A | FB-48
Steel Assembly | RIGID_FRAME | 325.4 | 16'-4"1/4 | 21'-1"5/8 | 5/B-A | FR-8
Steel Assembly | RIGID_FRAME | 1.7 | 18'-7"3/4 | 21'-4" | 2-3/B-A | FB-48
Steel Assembly | RIGID_FRAME | 1.7 | 18'-7"3/4 | 21'-4" | 1-2/B-A | FB-48
Steel Assembly | RIGID_FRAME | 325.4 | 16'-4"1/4 | 21'-1"5/8 | 2/B-A | FR-8
Steel Assembly | RIGID_FRAME | 1.7 | 18'-7"3/4 | 21'-4" | 6-7/B-A | FB-48
Steel Assembly | RIGID_FRAME | 1.7 | 18'-7"3/4 | 21'-4" | 5-6/B-A | FB-48
Steel Assembly | RIGID_FRAME | 325.4 | 16'-4"1/4 | 21'-1"5/8 | 6/B-A | FR-8
2 x Steel Assembly | RIGID_FRAME | 1.4 | 17'-2"13/16 | 20'-6"9/16 | 3-4/B-A | FB-60
Steel Assembly | RIGID_FRAME | 1.4 | 17'-2"13/16 | 20'-6"9/16 | 2-3/B-A | FB-60
2 x Steel Assembly | RIGID_FRAME | 1.4 | 17'-2"13/16 | 20'-6"9/16 | 4-5/B-A | FB-60
Steel Assembly | RIGID_FRAME | 1.4 | 17'-2"13/16 | 20'-6"9/16 | 5-6/B-A | FB-60
Steel Assembly | RIGID_FRAME | 1.9 | 17'-2"3/4 | 20'-6"9/16 | 2-3/B-A | FB-60
Steel Assembly | RIGID_FRAME | 1.9 | 17'-2"3/4 | 20'-6"9/16 | 1-2/B-A | FB-60
Steel Assembly | RIGID_FRAME | 1.9 | 17'-2"3/4 | 20'-6"9/16 | 6-7/B-A | FB-60
Steel Assembly | RIGID_FRAME | 1.9 | 17'-2"3/4 | 20'-6"9/16 | 5-6/B-A | FB-60
Steel Assembly | RIGID_FRAME | 1.2 | 19'-7"3/8 | 22'-2" | 2-3/C-B | FB-48
Steel Assembly | RIGID_FRAME | 1.7 | 19'-7"3/8 | 22'-2" | 5-6/C-B | FB-48
Steel Assembly | RIGID_FRAME | 1.2 | 20'-5"5/16 | 23'-0" | 2-3/C-B | FB-48
Steel Assembly | RIGID_FRAME | 1.7 | 20'-5"3/8 | 22'-11"15/16 | 5-6/C-B | FB-48
Steel Assembly | RIGID_FRAME | 1 | 5"3/16 | 8"3/16 | 3/A | BR-60
Steel Assembly | RIGID_FRAME | 0.1 | 4"5/16 | 6"1/4 | 3/A | BH-57
Steel Assembly | RIGID_FRAME | 0.1 | 4"11/16 | 6"7/16 | 3/A | BH-58
Steel Assembly | RIGID_FRAME | 1 | 5"3/16 | 8"3/16 | 2/A | BR-60
Steel Assembly | RIGID_FRAME | 0.1 | 4"5/16 | 6"1/4 | 2/A | BH-57
Steel Assembly | RIGID_FRAME | 0.1 | 4"11/16 | 6"7/16 | 2/A | BH-58
Steel Assembly | RIGID_FRAME | 1 | 18'-8"3/4 | 18'-11"3/4 | 3/A | BR-60
Steel Assembly | RIGID_FRAME | 0.1 | 18'-10"13/16 | 19'-0"3/4 | 3/A | BH-57
Steel Assembly | RIGID_FRAME | 0.1 | 18'-10"5/8 | 19'-0"3/8 | 3/A | BH-58
Steel Assembly | RIGID_FRAME | 1 | 18'-8"3/4 | 18'-11"3/4 | 2/A | BR-60
Steel Assembly | RIGID_FRAME | 0.1 | 18'-10"13/16 | 19'-0"3/4 | 2/A | BH-57
Steel Assembly | RIGID_FRAME | 0.1 | 18'-10"5/8 | 19'-0"3/8 | 2/A | BH-58
2 x Steel Assembly | RIGID_FRAME | 36.9 | 3"1/4 | 19'-1"13/16 | 2-3/A | R8-382
Steel Assembly | RIGID_FRAME | 1 | 5"3/16 | 8"3/16 | 6/A | BR-60
Steel Assembly | RIGID_FRAME | 0.1 | 4"5/16 | 6"1/4 | 6/A | BH-57
Steel Assembly | RIGID_FRAME | 0.1 | 4"11/16 | 6"7/16 | 6/A | BH-58
Steel Assembly | RIGID_FRAME | 1 | 5"3/16 | 8"3/16 | 5/A | BR-60
Steel Assembly | RIGID_FRAME | 0.1 | 4"5/16 | 6"1/4 | 5/A | BH-57
Steel Assembly | RIGID_FRAME | 0.1 | 4"11/16 | 6"7/16 | 5/A | BH-58
Steel Assembly | RIGID_FRAME | 1 | 18'-8"3/4 | 18'-11"3/4 | 6/A | BR-60
Steel Assembly | RIGID_FRAME | 0.1 | 18'-10"13/16 | 19'-0"3/4 | 6/A | BH-57
Steel Assembly | RIGID_FRAME | 0.1 | 18'-10"5/8 | 19'-0"3/8 | 6/A | BH-58
Steel Assembly | RIGID_FRAME | 1 | 18'-8"3/4 | 18'-11"3/4 | 5/A | BR-60
Steel Assembly | RIGID_FRAME | 0.1 | 18'-10"13/16 | 19'-0"3/4 | 5/A | BH-57
Steel Assembly | RIGID_FRAME | 0.1 | 18'-10"5/8 | 19'-0"3/8 | 5/A | BH-58
2 x Steel Assembly | RIGID_FRAME | 36.9 | 3"1/4 | 19'-1"13/16 | 5-6/A | R8-382
Steel Assembly | RIGID_FRAME | 1 | 18'-9"1/16 | 19'-0"1/16 | 5/G | BR-60
Steel Assembly | RIGID_FRAME | 0.1 | 18'-11" | 19'-0"15/16 | 5/G | BH-57
Steel Assembly | RIGID_FRAME | 0.1 | 18'-10"7/8 | 19'-0"9/16 | 5/G | BH-58
Steel Assembly | RIGID_FRAME | 1 | 18'-9"1/16 | 19'-0"1/16 | 6/G | BR-60
Steel Assembly | RIGID_FRAME | 0.1 | 18'-11" | 19'-0"15/16 | 6/G | BH-57
Steel Assembly | RIGID_FRAME | 0.1 | 18'-10"13/16 | 19'-0"9/16 | 6/G | BH-58
2 x Steel Assembly | RIGID_FRAME | 36.9 | 3"1/4 | 19'-2" | 5-6/G | R8-382
Steel Assembly | RIGID_FRAME | 1 | 5"3/16 | 8"3/16 | 2/G | BR-60
Steel Assembly | RIGID_FRAME | 0.1 | 4"5/16 | 6"1/4 | 2/G | BH-57
Steel Assembly | RIGID_FRAME | 0.1 | 4"11/16 | 6"7/16 | 2/G | BH-58
Steel Assembly | RIGID_FRAME | 1 | 18'-9"1/16 | 19'-0"1/16 | 2/G | BR-60
Steel Assembly | RIGID_FRAME | 0.1 | 18'-11" | 19'-0"15/16 | 2/G | BH-57
Steel Assembly | RIGID_FRAME | 0.1 | 18'-10"7/8 | 19'-0"9/16 | 2/G | BH-58
Steel Assembly | RIGID_FRAME | 1 | 18'-9"1/16 | 19'-0"1/16 | 3/G | BR-60
Steel Assembly | RIGID_FRAME | 0.1 | 18'-11" | 19'-0"15/16 | 3/G | BH-57
Steel Assembly | RIGID_FRAME | 0.1 | 18'-10"13/16 | 19'-0"9/16 | 3/G | BH-58
2 x Steel Assembly | RIGID_FRAME | 36.9 | 3"1/4 | 19'-2" | 2-3/G | R8-382
Steel Assembly | RIGID_FRAME | 1 | 22'-6"3/8 | 22'-8"3/8 | 3/C | BR-75
Steel Assembly | RIGID_FRAME | 0.1 | 22'-6"11/16 | 22'-7"15/16 | 3/C | BH-80
Steel Assembly | RIGID_FRAME | 0 | 22'-6"5/8 | 22'-8"1/16 | 3/C | BH-81
Steel Assembly | RIGID_FRAME | 1 | 22'-6"3/8 | 22'-8"3/8 | 2/C | BR-75
Steel Assembly | RIGID_FRAME | 0.1 | 22'-6"11/16 | 22'-7"15/16 | 2/C | BH-80
Steel Assembly | RIGID_FRAME | 0 | 22'-6"5/8 | 22'-8"1/16 | 2/C | BH-81
2 x Steel Assembly | RIGID_FRAME | 1 | 23'-4"5/8 | 23'-6"5/8 | 3/E-C | BR-75
2 x Steel Assembly | RIGID_FRAME | 0.1 | 23'-5"1/16 | 23'-6"5/16 | 3/E-C | BH-80
2 x Steel Assembly | RIGID_FRAME | 0 | 23'-4"15/16 | 23'-6"3/8 | 3/E-C | BH-81
2 x Steel Assembly | RIGID_FRAME | 1 | 23'-4"5/8 | 23'-6"5/8 | 2/E-C | BR-75
2 x Steel Assembly | RIGID_FRAME | 0.1 | 23'-5"1/16 | 23'-6"5/16 | 2/E-C | BH-80
2 x Steel Assembly | RIGID_FRAME | 0 | 23'-4"15/16 | 23'-6"3/8 | 2/E-C | BH-81
4 x Steel Assembly | RIGID_FRAME | 16.9 | 22'-7"1/4 | 23'-6"1/8 | 2-3/E-C | R6-331
Steel Assembly | RIGID_FRAME | 1 | 22'-6"3/8 | 22'-8"3/8 | 6/C | BR-75
Steel Assembly | RIGID_FRAME | 0.1 | 22'-6"11/16 | 22'-7"15/16 | 6/C | BH-80
Steel Assembly | RIGID_FRAME | 0 | 22'-6"5/8 | 22'-8"1/16 | 6/C | BH-81
Steel Assembly | RIGID_FRAME | 1 | 22'-6"3/8 | 22'-8"3/8 | 5/C | BR-75
Steel Assembly | RIGID_FRAME | 0.1 | 22'-6"11/16 | 22'-7"15/16 | 5/C | BH-80
Steel Assembly | RIGID_FRAME | 0 | 22'-6"5/8 | 22'-8"1/16 | 5/C | BH-81
2 x Steel Assembly | RIGID_FRAME | 1 | 23'-4"5/8 | 23'-6"5/8 | 6/E-C | BR-75
2 x Steel Assembly | RIGID_FRAME | 0.1 | 23'-5"1/16 | 23'-6"5/16 | 6/E-C | BH-80
2 x Steel Assembly | RIGID_FRAME | 0 | 23'-4"15/16 | 23'-6"3/8 | 6/E-C | BH-81
2 x Steel Assembly | RIGID_FRAME | 1 | 23'-4"5/8 | 23'-6"5/8 | 5/E-C | BR-75
2 x Steel Assembly | RIGID_FRAME | 0.1 | 23'-5"1/16 | 23'-6"5/16 | 5/E-C | BH-80
2 x Steel Assembly | RIGID_FRAME | 0 | 23'-4"15/16 | 23'-6"3/8 | 5/E-C | BH-81
4 x Steel Assembly | RIGID_FRAME | 16.9 | 22'-7"1/4 | 23'-6"1/8 | 5-6/E-C | R6-331
Steel Assembly | RIGID_FRAME | 1 | 22'-6"3/8 | 22'-8"3/8 | 5/E | BR-75
Steel Assembly | RIGID_FRAME | 0.1 | 22'-6"11/16 | 22'-7"15/16 | 5/E | BH-80
Steel Assembly | RIGID_FRAME | 0 | 22'-6"5/8 | 22'-8"1/16 | 5/E | BH-81
Steel Assembly | RIGID_FRAME | 1 | 22'-6"3/8 | 22'-8"3/8 | 6/E | BR-75
Steel Assembly | RIGID_FRAME | 0.1 | 22'-6"11/16 | 22'-7"15/16 | 6/E | BH-80
Steel Assembly | RIGID_FRAME | 0 | 22'-6"5/8 | 22'-8"1/16 | 6/E | BH-81
Steel Assembly | RIGID_FRAME | 1 | 22'-6"3/8 | 22'-8"3/8 | 2/E | BR-75
Steel Assembly | RIGID_FRAME | 0.1 | 22'-6"11/16 | 22'-7"15/16 | 2/E | BH-80
Steel Assembly | RIGID_FRAME | 0 | 22'-6"5/8 | 22'-8"1/16 | 2/E | BH-81
Steel Assembly | RIGID_FRAME | 1 | 22'-6"3/8 | 22'-8"3/8 | 3/E | BR-75
Steel Assembly | RIGID_FRAME | 0.1 | 22'-6"11/16 | 22'-7"15/16 | 3/E | BH-80
Steel Assembly | RIGID_FRAME | 0 | 22'-6"5/8 | 22'-8"1/16 | 3/E | BH-81
Steel Assembly | RIGID_FRAME | 1 | 22'-5"3/4 | 22'-7"3/4 | 3/E | BR-75
Steel Assembly | RIGID_FRAME | 0.1 | 22'-6"1/4 | 22'-7"1/2 | 3/E | BH-80
Steel Assembly | RIGID_FRAME | 0 | 22'-6"1/8 | 22'-7"9/16 | 3/E | BH-81
Steel Assembly | RIGID_FRAME | 1 | 22'-5"3/4 | 22'-7"3/4 | 2/E | BR-75
Steel Assembly | RIGID_FRAME | 0.1 | 22'-6"1/4 | 22'-7"1/2 | 2/E | BH-80
Steel Assembly | RIGID_FRAME | 0 | 22'-6"1/8 | 22'-7"9/16 | 2/E | BH-81
Steel Assembly | RIGID_FRAME | 1 | 20'-10"13/16 | 21'-0"13/16 | 3/F | BR-75
Steel Assembly | RIGID_FRAME | 0.1 | 20'-11"1/16 | 21'-0"3/8 | 3/F | BH-80
Steel Assembly | RIGID_FRAME | 0 | 20'-11" | 21'-0"7/16 | 3/F | BH-81
Steel Assembly | RIGID_FRAME | 1 | 20'-11" | 21'-1" | 2/F | BR-75
Steel Assembly | RIGID_FRAME | 0.1 | 20'-11"1/16 | 21'-0"3/8 | 2/F | BH-80
Steel Assembly | RIGID_FRAME | 0 | 20'-11" | 21'-0"7/16 | 2/F | BH-81
2 x Steel Assembly | RIGID_FRAME | 19.7 | 20'-11"1/4 | 22'-7"3/8 | 2-3/F-E | R6-385
Steel Assembly | RIGID_FRAME | 1 | 22'-5"3/4 | 22'-7"3/4 | 6/E | BR-75
Steel Assembly | RIGID_FRAME | 0.1 | 22'-6"1/4 | 22'-7"1/2 | 6/E | BH-80
Steel Assembly | RIGID_FRAME | 0 | 22'-6"1/8 | 22'-7"9/16 | 6/E | BH-81
Steel Assembly | RIGID_FRAME | 1 | 22'-5"3/4 | 22'-7"3/4 | 5/E | BR-75
Steel Assembly | RIGID_FRAME | 0.1 | 22'-6"1/4 | 22'-7"1/2 | 5/E | BH-80
Steel Assembly | RIGID_FRAME | 0 | 22'-6"1/8 | 22'-7"9/16 | 5/E | BH-81
Steel Assembly | RIGID_FRAME | 1 | 20'-10"13/16 | 21'-0"13/16 | 6/F | BR-75
Steel Assembly | RIGID_FRAME | 0.1 | 20'-11"1/16 | 21'-0"3/8 | 6/F | BH-80
Steel Assembly | RIGID_FRAME | 0 | 20'-11" | 21'-0"7/16 | 6/F | BH-81
2 x Steel Assembly | RIGID_FRAME | 19.7 | 20'-11"1/4 | 22'-7"3/8 | 5-6/F-E | R6-385
Steel Assembly | RIGID_FRAME | 1 | 22'-5"3/4 | 22'-7"3/4 | 2/C | BR-75
Steel Assembly | RIGID_FRAME | 0.1 | 22'-6"1/4 | 22'-7"1/2 | 2/C | BH-80
Steel Assembly | RIGID_FRAME | 0 | 22'-6"1/8 | 22'-7"9/16 | 2/C | BH-81
Steel Assembly | RIGID_FRAME | 1 | 22'-5"3/4 | 22'-7"3/4 | 3/C | BR-75
Steel Assembly | RIGID_FRAME | 0.1 | 22'-6"1/4 | 22'-7"1/2 | 3/C | BH-80
Steel Assembly | RIGID_FRAME | 0 | 22'-6"1/8 | 22'-7"9/16 | 3/C | BH-81
Steel Assembly | RIGID_FRAME | 1 | 20'-10"13/16 | 21'-0"13/16 | 3/B | BR-75
Steel Assembly | RIGID_FRAME | 0.1 | 20'-11"1/16 | 21'-0"3/8 | 3/B | BH-80
Steel Assembly | RIGID_FRAME | 0 | 20'-11" | 21'-0"7/16 | 3/B | BH-81
2 x Steel Assembly | RIGID_FRAME | 19.7 | 20'-11"1/4 | 22'-7"3/8 | 2-3/C-B | R6-385
Steel Assembly | RIGID_FRAME | 1 | 22'-5"3/4 | 22'-7"3/4 | 5/C | BR-75
Steel Assembly | RIGID_FRAME | 0.1 | 22'-6"1/4 | 22'-7"1/2 | 5/C | BH-80
Steel Assembly | RIGID_FRAME | 0 | 22'-6"1/8 | 22'-7"9/16 | 5/C | BH-81
Steel Assembly | RIGID_FRAME | 1 | 22'-5"3/4 | 22'-7"3/4 | 6/C | BR-75
Steel Assembly | RIGID_FRAME | 0.1 | 22'-6"1/4 | 22'-7"1/2 | 6/C | BH-80
Steel Assembly | RIGID_FRAME | 0 | 22'-6"1/8 | 22'-7"9/16 | 6/C | BH-81
Steel Assembly | RIGID_FRAME | 1 | 20'-10"13/16 | 21'-0"13/16 | 5/B | BR-75
Steel Assembly | RIGID_FRAME | 0.1 | 20'-11"1/16 | 21'-0"3/8 | 5/B | BH-80
Steel Assembly | RIGID_FRAME | 0 | 20'-11" | 21'-0"7/16 | 5/B | BH-81
Steel Assembly | RIGID_FRAME | 1 | 20'-10"13/16 | 21'-0"13/16 | 6/B | BR-75
Steel Assembly | RIGID_FRAME | 0.1 | 20'-11"1/16 | 21'-0"3/8 | 6/B | BH-80
Steel Assembly | RIGID_FRAME | 0 | 20'-11" | 21'-0"7/16 | 6/B | BH-81
2 x Steel Assembly | RIGID_FRAME | 19.7 | 20'-11"1/4 | 22'-7"3/8 | 5-6/C-B | R6-385
Steel Assembly | RIGID_FRAME | 1 | 20'-9"15/16 | 20'-11"7/8 | 3/B | BR-75
Steel Assembly | RIGID_FRAME | 0.1 | 20'-10"3/8 | 20'-11"11/16 | 3/B | BH-80
Steel Assembly | RIGID_FRAME | 0 | 20'-10"1/4 | 20'-11"3/4 | 3/B | BH-81
Steel Assembly | RIGID_FRAME | 1 | 19'-1"7/8 | 19'-3"7/8 | 3/A | BR-75
Steel Assembly | RIGID_FRAME | 0.1 | 19'-2"1/8 | 19'-3"3/8 | 3/A | BH-80
Steel Assembly | RIGID_FRAME | 0 | 19'-2"1/16 | 19'-3"1/2 | 3/A | BH-81
Steel Assembly | RIGID_FRAME | 1 | 19'-1"7/8 | 19'-3"7/8 | 2/A | BR-75
Steel Assembly | RIGID_FRAME | 0.1 | 19'-2"1/8 | 19'-3"3/8 | 2/A | BH-80
Steel Assembly | RIGID_FRAME | 0 | 19'-2"1/16 | 19'-3"1/2 | 2/A | BH-81
2 x Steel Assembly | RIGID_FRAME | 20.1 | 19'-2"1/4 | 20'-11"1/2 | 2-3/B-A | R6-393
Steel Assembly | RIGID_FRAME | 1 | 20'-9"15/16 | 20'-11"7/8 | 6/B | BR-75
Steel Assembly | RIGID_FRAME | 0.1 | 20'-10"3/8 | 20'-11"11/16 | 6/B | BH-80
Steel Assembly | RIGID_FRAME | 0 | 20'-10"1/4 | 20'-11"3/4 | 6/B | BH-81
Steel Assembly | RIGID_FRAME | 1 | 20'-9"15/16 | 20'-11"15/16 | 5/B | BR-75
Steel Assembly | RIGID_FRAME | 0.1 | 20'-10"3/8 | 20'-11"11/16 | 5/B | BH-80
Steel Assembly | RIGID_FRAME | 0 | 20'-10"1/4 | 20'-11"3/4 | 5/B | BH-81
Steel Assembly | RIGID_FRAME | 1 | 19'-1"7/8 | 19'-3"7/8 | 6/A | BR-75
Steel Assembly | RIGID_FRAME | 0.1 | 19'-2"1/8 | 19'-3"3/8 | 6/A | BH-80
Steel Assembly | RIGID_FRAME | 0 | 19'-2"1/16 | 19'-3"1/2 | 6/A | BH-81
Steel Assembly | RIGID_FRAME | 1 | 19'-1"7/8 | 19'-3"7/8 | 5/A | BR-75
Steel Assembly | RIGID_FRAME | 0.1 | 19'-2"1/8 | 19'-3"3/8 | 5/A | BH-80
Steel Assembly | RIGID_FRAME | 0 | 19'-2"1/16 | 19'-3"1/2 | 5/A | BH-81
2 x Steel Assembly | RIGID_FRAME | 20.1 | 19'-2"1/4 | 20'-11"1/2 | 5-6/B-A | R6-393
Steel Assembly | RIGID_FRAME | 1 | 20'-9"15/16 | 20'-11"15/16 | 6/F | BR-75
Steel Assembly | RIGID_FRAME | 0.1 | 20'-10"7/16 | 20'-11"11/16 | 6/F | BH-80
Steel Assembly | RIGID_FRAME | 0 | 20'-10"5/16 | 20'-11"3/4 | 6/F | BH-81
Steel Assembly | RIGID_FRAME | 1 | 19'-2"3/16 | 19'-4"3/16 | 5/G-F | BR-75
Steel Assembly | RIGID_FRAME | 0.1 | 19'-2"7/16 | 19'-3"11/16 | 5/G | BH-80
Steel Assembly | RIGID_FRAME | 0 | 19'-2"3/8 | 19'-3"13/16 | 5/G | BH-81
Steel Assembly | RIGID_FRAME | 1 | 19'-2"3/16 | 19'-4"3/16 | 6/G-F | BR-75
Steel Assembly | RIGID_FRAME | 0.1 | 19'-2"7/16 | 19'-3"11/16 | 6/G | BH-80
Steel Assembly | RIGID_FRAME | 0 | 19'-2"3/8 | 19'-3"13/16 | 6/G | BH-81
2 x Steel Assembly | RIGID_FRAME | 20 | 19'-2"5/8 | 20'-11"1/2 | 5-6/G-F | R6-391
Steel Assembly | RIGID_FRAME | 1 | 20'-9"15/16 | 20'-11"15/16 | 3/F | BR-75
Steel Assembly | RIGID_FRAME | 0.1 | 20'-10"7/16 | 20'-11"11/16 | 3/F | BH-80
Steel Assembly | RIGID_FRAME | 0 | 20'-10"5/16 | 20'-11"3/4 | 3/F | BH-81
Steel Assembly | RIGID_FRAME | 1 | 19'-2"3/16 | 19'-4"3/16 | 2/G-F | BR-75
Steel Assembly | RIGID_FRAME | 0.1 | 19'-2"7/16 | 19'-3"11/16 | 2/G | BH-80
Steel Assembly | RIGID_FRAME | 0 | 19'-2"3/8 | 19'-3"13/16 | 2/G | BH-81
Steel Assembly | RIGID_FRAME | 1 | 19'-2"3/16 | 19'-4"3/16 | 3/G-F | BR-75
Steel Assembly | RIGID_FRAME | 0.1 | 19'-2"7/16 | 19'-3"11/16 | 3/G | BH-80
Steel Assembly | RIGID_FRAME | 0 | 19'-2"3/8 | 19'-3"13/16 | 3/G | BH-81
2 x Steel Assembly | RIGID_FRAME | 20 | 19'-2"5/8 | 20'-11"1/2 | 2-3/G-F | R6-391
Steel Assembly | RIGID_FRAME | 23.2 | 19'-9" | 20'-3" | 7/F-E | ZW-13
Steel Assembly | RIGID_FRAME | 9.5 | 19'-9" | 20'-3" | 7/G-F | ZW-12
Steel Assembly | RIGID_FRAME | 3.4 | 17'-6"1/16 | 17'-9"1/16 | 1/A | AC-150
Steel Assembly | RIGID_FRAME | 22.7 | 17'-3" | 17'-9" | 1/B-A | ZT-5
Steel Assembly | RIGID_FRAME | 3.4 | 20'-0"1/16 | 20'-3"1/16 | 7/G-F | AC-150
Steel Assembly | RIGID_FRAME | 1.2 | 7'-6" | 7'-9" | 7/A | AC-01R
Steel Assembly | RIGID_FRAME | 57.1 | 13'-5" | 13'-11" | 1-3/A | ZS-2
Steel Assembly | RIGID_FRAME | 1.2 | 13'-8" | 13'-11" | 1/A | AC-01R
Steel Assembly | RIGID_FRAME | 57.1 | 13'-5" | 13'-11" | 5-7/A | ZS-3
Steel Assembly | RIGID_FRAME | 1.2 | 13'-8" | 13'-11" | 7/A | AC-01R
Steel Assembly | RIGID_FRAME | 11.1 | 7'-3" | 7'-9" | 1-3/A | ZW-3
Steel Assembly | RIGID_FRAME | 1.2 | 7'-6" | 7'-8"3/4 | 2/A | AC-01R
Steel Assembly | RIGID_FRAME | 1.2 | 13'-8" | 13'-10"3/4 | 2/A | AC-01R
Steel Assembly | RIGID_FRAME | 43.4 | 13'-5" | 13'-11" | 1-4/A | ZT-6
Steel Assembly | RIGID_FRAME | 1.2 | 13'-8" | 13'-10"3/4 | 3/A | AC-01R
Steel Assembly | RIGID_FRAME | 38.9 | 7'-3" | 7'-9" | 1-4/A | ZW-8
Steel Assembly | RIGID_FRAME | 1.2 | 7'-6" | 7'-8"3/4 | 3/A | AC-01R
Steel Assembly | RIGID_FRAME | 37.6 | 7'-3" | 7'-9" | 2-5/A | ZW-10
Steel Assembly | RIGID_FRAME | 1.2 | 7'-6" | 7'-8"3/4 | 4/A | AC-01R
Steel Assembly | RIGID_FRAME | 37.6 | 13'-5" | 13'-11" | 2-5/A | ZW-10
Steel Assembly | RIGID_FRAME | 1.2 | 13'-8" | 13'-10"3/4 | 4/A | AC-01R
Steel Assembly | RIGID_FRAME | 37.6 | 13'-5" | 13'-11" | 3-6/A | ZW-10
Steel Assembly | RIGID_FRAME | 1.2 | 13'-8" | 13'-10"3/4 | 5/A | AC-01R
Steel Assembly | RIGID_FRAME | 37.6 | 7'-3" | 7'-9" | 3-6/A | ZW-10
Steel Assembly | RIGID_FRAME | 1.2 | 7'-6" | 7'-8"3/4 | 5/A | AC-01R
Steel Assembly | RIGID_FRAME | 43.4 | 13'-5" | 13'-11" | 4-7/A | ZT-7
Steel Assembly | RIGID_FRAME | 1.2 | 13'-8" | 13'-10"3/4 | 6/A | AC-01R
Steel Assembly | RIGID_FRAME | 54.9 | 19'-4"13/16 | 20'-1"3/16 | 2-3/G | ZS-1
Steel Assembly | RIGID_FRAME | 1.2 | 19'-5" | 20'-0"1/4 | 2/G | AC-01R
Steel Assembly | RIGID_FRAME | 54.9 | 19'-4"13/16 | 20'-1"3/16 | 5-6/G | ZS-1
Steel Assembly | RIGID_FRAME | 1.2 | 19'-5" | 20'-0"1/4 | 5/G | AC-01R
Steel Assembly | RIGID_FRAME | 54.9 | 19'-4"13/16 | 20'-1"3/16 | 5-6/A | ZS-1
Steel Assembly | RIGID_FRAME | 1.2 | 19'-5" | 20'-0"1/4 | 6/A | AC-01R
Steel Assembly | RIGID_FRAME | 54.9 | 19'-4"13/16 | 20'-1"3/16 | 2-3/A | ZS-1
Steel Assembly | RIGID_FRAME | 1.2 | 19'-5" | 20'-0"1/4 | 3/A | AC-01R
Steel Assembly | RIGID_FRAME | 1.2 | 19'-5" | 20'-0"1/4 | 2/A | AC-01R
Steel Assembly | RIGID_FRAME | 1.2 | 19'-5" | 20'-0"1/4 | 5/A | AC-01R
Steel Assembly | RIGID_FRAME | 1.2 | 19'-5" | 20'-0"1/4 | 6/G | AC-01R
Steel Assembly | RIGID_FRAME | 1.2 | 19'-5" | 20'-0"1/4 | 3/G | AC-01R
Steel Assembly | RIGID_FRAME | 53.5 | 19'-6"1/2 | 20'-2"7/8 | 1-3/B-A | ZX-2
Steel Assembly | RIGID_FRAME | 53.5 | 20'-3"7/16 | 20'-11"7/8 | 1-3/B-A | ZX-2
Steel Assembly | RIGID_FRAME | 53.5 | 20'-8"7/16 | 21'-4"13/16 | 1-3/B-A | ZX-2
Steel Assembly | RIGID_FRAME | 53.5 | 19'-6"1/2 | 20'-2"7/8 | 5-7/G-F | ZX-2
Steel Assembly | RIGID_FRAME | 53.5 | 20'-3"7/16 | 20'-11"7/8 | 5-7/G-F | ZX-2
Steel Assembly | RIGID_FRAME | 53.5 | 20'-8"7/16 | 21'-4"13/16 | 5-7/G-F | ZX-2
Steel Assembly | RIGID_FRAME | 53.5 | 21'-1"7/16 | 21'-9"13/16 | 5-7/F | ZX-2
Steel Assembly | RIGID_FRAME | 53.5 | 21'-6"7/16 | 22'-2"13/16 | 5-7/F-E | ZX-2
Steel Assembly | RIGID_FRAME | 53.5 | 21'-11"3/8 | 22'-7"3/4 | 5-7/F-E | ZX-2
Steel Assembly | RIGID_FRAME | 53.5 | 22'-4"3/8 | 23'-0"3/4 | 5-7/F-E | ZX-2
Steel Assembly | RIGID_FRAME | 53.5 | 22'-9"3/8 | 23'-5"3/4 | 5-7/E | ZX-2
Steel Assembly | RIGID_FRAME | 53.5 | 23'-2"5/16 | 23'-10"3/4 | 5-7/E-C | ZX-2
Steel Assembly | RIGID_FRAME | 53.5 | 23'-7"5/16 | 24'-3"11/16 | 5-7/E-C | ZX-2
Steel Assembly | RIGID_FRAME | 53.5 | 19'-6"1/2 | 20'-2"7/8 | 5-7/B-A | ZX-1
Steel Assembly | RIGID_FRAME | 53.5 | 20'-3"7/16 | 20'-11"7/8 | 5-7/B-A | ZX-1
Steel Assembly | RIGID_FRAME | 53.5 | 20'-8"7/16 | 21'-4"13/16 | 5-7/B-A | ZX-1
Steel Assembly | RIGID_FRAME | 53.5 | 21'-1"7/16 | 21'-9"13/16 | 5-7/B | ZX-1
Steel Assembly | RIGID_FRAME | 53.5 | 21'-6"7/16 | 22'-2"13/16 | 5-7/C-B | ZX-1
Steel Assembly | RIGID_FRAME | 53.5 | 21'-11"3/8 | 22'-7"3/4 | 5-7/C-B | ZX-1
Steel Assembly | RIGID_FRAME | 53.5 | 22'-4"3/8 | 23'-0"3/4 | 5-7/C-B | ZX-1
Steel Assembly | RIGID_FRAME | 53.5 | 22'-9"3/8 | 23'-5"3/4 | 5-7/C | ZX-1
Steel Assembly | RIGID_FRAME | 53.5 | 23'-2"5/16 | 23'-10"3/4 | 5-7/E-C | ZX-1
Steel Assembly | RIGID_FRAME | 53.5 | 23'-7"5/16 | 24'-3"11/16 | 5-7/E-C | ZX-1
Steel Assembly | RIGID_FRAME | 53.5 | 23'-7"5/16 | 24'-3"11/16 | 1-3/E-C | ZX-1
Steel Assembly | RIGID_FRAME | 53.5 | 23'-2"5/16 | 23'-10"3/4 | 1-3/E-C | ZX-1
Steel Assembly | RIGID_FRAME | 53.5 | 22'-9"3/8 | 23'-5"3/4 | 1-3/E | ZX-1
Steel Assembly | RIGID_FRAME | 53.5 | 22'-4"3/8 | 23'-0"3/4 | 1-3/F-E | ZX-1
Steel Assembly | RIGID_FRAME | 53.5 | 21'-11"3/8 | 22'-7"3/4 | 1-3/F-E | ZX-1
Steel Assembly | RIGID_FRAME | 53.5 | 21'-6"7/16 | 22'-2"13/16 | 1-3/F-E | ZX-1
Steel Assembly | RIGID_FRAME | 53.5 | 21'-1"7/16 | 21'-9"13/16 | 1-3/F | ZX-1
Steel Assembly | RIGID_FRAME | 53.5 | 19'-6"1/2 | 20'-2"7/8 | 1-3/G-F | ZX-1
Steel Assembly | RIGID_FRAME | 45.8 | 19'-6"1/2 | 20'-2"7/8 | 4-7/G-F | ZT-2
Steel Assembly | RIGID_FRAME | 45.8 | 19'-11" | 20'-7"3/8 | 4-7/G-F | ZT-2
Steel Assembly | RIGID_FRAME | 45.8 | 20'-3"7/16 | 20'-11"7/8 | 4-7/G-F | ZT-2
Steel Assembly | RIGID_FRAME | 45.8 | 20'-8"7/16 | 21'-4"13/16 | 4-7/G-F | ZT-2
Steel Assembly | RIGID_FRAME | 45.8 | 23'-7"5/16 | 24'-3"11/16 | 4-7/E-C | ZT-1
Steel Assembly | RIGID_FRAME | 45.8 | 23'-2"5/16 | 23'-10"3/4 | 4-7/E-C | ZT-1
Steel Assembly | RIGID_FRAME | 45.8 | 22'-9"3/8 | 23'-5"3/4 | 4-7/C | ZT-1
Steel Assembly | RIGID_FRAME | 45.8 | 22'-4"3/8 | 23'-0"3/4 | 4-7/C-B | ZT-1
Steel Assembly | RIGID_FRAME | 45.8 | 21'-11"3/8 | 22'-7"3/4 | 4-7/C-B | ZT-1
Steel Assembly | RIGID_FRAME | 45.8 | 21'-6"7/16 | 22'-2"13/16 | 4-7/C-B | ZT-1
Steel Assembly | RIGID_FRAME | 45.8 | 21'-1"7/16 | 21'-9"13/16 | 4-7/B | ZT-1
Steel Assembly | RIGID_FRAME | 45.8 | 20'-8"7/16 | 21'-4"13/16 | 4-7/B-A | ZT-1
Steel Assembly | RIGID_FRAME | 45.8 | 20'-3"7/16 | 20'-11"7/8 | 4-7/B-A | ZT-1
Steel Assembly | RIGID_FRAME | 45.8 | 19'-11" | 20'-7"3/8 | 4-7/B-A | ZT-1
Steel Assembly | RIGID_FRAME | 45.8 | 19'-6"1/2 | 20'-2"7/8 | 4-7/B-A | ZT-1
Steel Assembly | RIGID_FRAME | 45.8 | 19'-6"1/2 | 20'-2"7/8 | 1-4/B-A | ZT-2
Steel Assembly | RIGID_FRAME | 45.8 | 19'-11" | 20'-7"3/8 | 1-4/B-A | ZT-2
Steel Assembly | RIGID_FRAME | 45.8 | 20'-3"7/16 | 20'-11"7/8 | 1-4/B-A | ZT-2
Steel Assembly | RIGID_FRAME | 45.8 | 20'-8"7/16 | 21'-4"13/16 | 1-4/B-A | ZT-2
Steel Assembly | RIGID_FRAME | 45.8 | 21'-1"7/16 | 21'-9"13/16 | 1-4/B | ZT-2
Steel Assembly | RIGID_FRAME | 45.8 | 21'-6"7/16 | 22'-2"13/16 | 1-4/C-B | ZT-2
Steel Assembly | RIGID_FRAME | 45.8 | 21'-11"3/8 | 22'-7"3/4 | 1-4/C-B | ZT-2
Steel Assembly | RIGID_FRAME | 45.8 | 22'-4"3/8 | 23'-0"3/4 | 1-4/C-B | ZT-2
Steel Assembly | RIGID_FRAME | 45.8 | 22'-9"3/8 | 23'-5"3/4 | 1-4/C | ZT-2
Steel Assembly | RIGID_FRAME | 45.8 | 23'-2"5/16 | 23'-10"3/4 | 1-4/E-C | ZT-2
Steel Assembly | RIGID_FRAME | 45.8 | 23'-7"5/16 | 24'-3"11/16 | 1-4/E-C | ZT-2
Steel Assembly | RIGID_FRAME | 45.8 | 20'-8"7/16 | 21'-4"13/16 | 1-4/G-F | ZT-1
Steel Assembly | RIGID_FRAME | 45.8 | 20'-3"7/16 | 20'-11"7/8 | 1-4/G-F | ZT-1
Steel Assembly | RIGID_FRAME | 45.8 | 19'-11" | 20'-7"3/8 | 1-4/G-F | ZT-1
Steel Assembly | RIGID_FRAME | 45.8 | 19'-6"1/2 | 20'-2"7/8 | 1-4/G-F | ZT-1
2 x Steel Assembly | RIGID_FRAME | 43.9 | 23'-7"5/16 | 24'-3"11/16 | 3-6/E-C | ZT-3
2 x Steel Assembly | RIGID_FRAME | 43.9 | 23'-2"5/16 | 23'-10"3/4 | 3-6/E-C | ZT-3
Steel Assembly | RIGID_FRAME | 43.9 | 22'-9"3/8 | 23'-5"3/4 | 3-6/E | ZT-3
Steel Assembly | RIGID_FRAME | 43.9 | 22'-4"3/8 | 23'-0"3/4 | 3-6/F-E | ZT-3
Steel Assembly | RIGID_FRAME | 43.9 | 21'-11"3/8 | 22'-7"3/4 | 3-6/F-E | ZT-3
Steel Assembly | RIGID_FRAME | 43.9 | 21'-6"7/16 | 22'-2"13/16 | 3-6/F-E | ZT-3
Steel Assembly | RIGID_FRAME | 43.9 | 21'-1"7/16 | 21'-9"13/16 | 3-6/F | ZT-3
Steel Assembly | RIGID_FRAME | 43.9 | 20'-8"7/16 | 21'-4"13/16 | 3-6/G-F | ZT-3
Steel Assembly | RIGID_FRAME | 43.9 | 20'-3"7/16 | 20'-11"7/8 | 3-6/G-F | ZT-3
Steel Assembly | RIGID_FRAME | 43.9 | 19'-11" | 20'-7"3/8 | 3-6/G-F | ZT-3
Steel Assembly | RIGID_FRAME | 43.9 | 19'-6"1/2 | 20'-2"7/8 | 3-6/G-F | ZT-3
Steel Assembly | RIGID_FRAME | 43.9 | 19'-6"1/2 | 20'-2"7/8 | 2-5/G-F | ZT-3
Steel Assembly | RIGID_FRAME | 43.9 | 19'-11" | 20'-7"3/8 | 2-5/G-F | ZT-3
Steel Assembly | RIGID_FRAME | 43.9 | 20'-3"7/16 | 20'-11"7/8 | 2-5/G-F | ZT-3
Steel Assembly | RIGID_FRAME | 43.9 | 20'-8"7/16 | 21'-4"13/16 | 2-5/G-F | ZT-3
Steel Assembly | RIGID_FRAME | 43.9 | 21'-1"7/16 | 21'-9"13/16 | 2-5/F | ZT-3
Steel Assembly | RIGID_FRAME | 43.9 | 21'-6"7/16 | 22'-2"13/16 | 2-5/F-E | ZT-3
Steel Assembly | RIGID_FRAME | 43.9 | 21'-11"3/8 | 22'-7"3/4 | 2-5/F-E | ZT-3
Steel Assembly | RIGID_FRAME | 43.9 | 22'-4"3/8 | 23'-0"3/4 | 2-5/F-E | ZT-3
Steel Assembly | RIGID_FRAME | 43.9 | 22'-9"3/8 | 23'-5"3/4 | 2-5/E | ZT-3
Steel Assembly | RIGID_FRAME | 43.9 | 19'-6"1/2 | 20'-2"7/8 | 3-6/B-A | ZT-3
Steel Assembly | RIGID_FRAME | 43.9 | 19'-11" | 20'-7"3/8 | 3-6/B-A | ZT-3
Steel Assembly | RIGID_FRAME | 43.9 | 20'-3"7/16 | 20'-11"7/8 | 3-6/B-A | ZT-3
Steel Assembly | RIGID_FRAME | 43.9 | 20'-8"7/16 | 21'-4"13/16 | 3-6/B-A | ZT-3
Steel Assembly | RIGID_FRAME | 43.9 | 21'-1"7/16 | 21'-9"13/16 | 3-6/B | ZT-3
Steel Assembly | RIGID_FRAME | 43.9 | 21'-6"7/16 | 22'-2"13/16 | 3-6/C-B | ZT-3
Steel Assembly | RIGID_FRAME | 43.9 | 21'-11"3/8 | 22'-7"3/4 | 3-6/C-B | ZT-3
Steel Assembly | RIGID_FRAME | 43.9 | 22'-4"3/8 | 23'-0"3/4 | 3-6/C-B | ZT-3
Steel Assembly | RIGID_FRAME | 43.9 | 22'-9"3/8 | 23'-5"3/4 | 3-6/C | ZT-3
Steel Assembly | RIGID_FRAME | 43.9 | 19'-6"1/2 | 20'-2"7/8 | 2-5/B-A | ZT-3
Steel Assembly | RIGID_FRAME | 43.9 | 19'-11" | 20'-7"3/8 | 2-5/B-A | ZT-3
Steel Assembly | RIGID_FRAME | 43.9 | 20'-3"7/16 | 20'-11"7/8 | 2-5/B-A | ZT-3
Steel Assembly | RIGID_FRAME | 43.9 | 20'-8"7/16 | 21'-4"13/16 | 2-5/B-A | ZT-3
Steel Assembly | RIGID_FRAME | 55.4 | 19'-4" | 20'-0"5/16 | 6-7/G | GE8-2
Steel Assembly | RIGID_FRAME | 55.4 | 19'-4" | 20'-0"5/16 | 1-2/A | GE8-2
Steel Assembly | RIGID_FRAME | 55.4 | 19'-4" | 20'-0"5/16 | 6-7/A | GE8-1
Steel Assembly | RIGID_FRAME | 58.3 | 19'-4" | 20'-0"5/16 | 5-6/A | GE8-3
Steel Assembly | RIGID_FRAME | 2.3 | 19'-4"1/8 | 19'-4"7/8 | 6/A | AC-13
Steel Assembly | RIGID_FRAME | 58.3 | 19'-4" | 20'-0"5/16 | 4-5/A | GE8-3
Steel Assembly | RIGID_FRAME | 2.3 | 19'-4"1/8 | 19'-4"7/8 | 5/A | AC-13
Steel Assembly | RIGID_FRAME | 58.3 | 19'-4" | 20'-0"5/16 | 3-4/A | GE8-3
Steel Assembly | RIGID_FRAME | 2.3 | 19'-4"1/8 | 19'-4"7/8 | 4/A | AC-13
Steel Assembly | RIGID_FRAME | 58.3 | 19'-4" | 20'-0"5/16 | 2-3/A | GE8-3
Steel Assembly | RIGID_FRAME | 2.3 | 19'-4"1/8 | 19'-4"7/8 | 3/A | AC-13
Steel Assembly | RIGID_FRAME | 2.3 | 19'-4"1/8 | 19'-4"7/8 | 2/A | AC-13
Steel Assembly | RIGID_FRAME | 55.4 | 19'-4" | 20'-0"5/16 | 1-2/G | GE8-1
Steel Assembly | RIGID_FRAME | 58.3 | 19'-4" | 20'-0"5/16 | 2-3/G | GE8-3
Steel Assembly | RIGID_FRAME | 2.3 | 19'-4"1/8 | 19'-4"7/8 | 2/G | AC-13
Steel Assembly | RIGID_FRAME | 58.3 | 19'-4" | 20'-0"5/16 | 3-4/G | GE8-3
Steel Assembly | RIGID_FRAME | 2.3 | 19'-4"1/8 | 19'-4"7/8 | 3/G | AC-13
Steel Assembly | RIGID_FRAME | 58.3 | 19'-4" | 20'-0"5/16 | 4-5/G | GE8-3
Steel Assembly | RIGID_FRAME | 2.3 | 19'-4"1/8 | 19'-4"7/8 | 4/G | AC-13
Steel Assembly | RIGID_FRAME | 58.3 | 19'-4" | 20'-0"5/16 | 5-6/G | GE8-3
Steel Assembly | RIGID_FRAME | 2.3 | 19'-4"1/8 | 19'-4"7/8 | 5/G | AC-13
Steel Assembly | RIGID_FRAME | 2.3 | 19'-4"1/8 | 19'-4"7/8 | 6/G | AC-13
Steel Assembly | RIGID_FRAME | 22.7 | 13'-5" | 13'-11" | 1/B-A | ZT-4
Steel Assembly | RIGID_FRAME | 23.6 | 13'-5" | 13'-11" | 7/B-A | ZT-9
Steel Assembly | RIGID_FRAME | 28.3 | 19'-9" | 20'-3" | 7/C-A | ZW-14
Steel Assembly | RIGID_FRAME | 42 | 13'-5" | 13'-11" | 7/C-A | ZX-8
Steel Assembly | RIGID_FRAME | 25.9 | 13'-5" | 13'-11" | 7/F-E | ZT-8
Steel Assembly | RIGID_FRAME | 35 | 13'-5" | 13'-11" | 2-4/G | ZW-4
Steel Assembly | RIGID_FRAME | 8.2 | 13'-5" | 13'-11" | 1-2/G | ZW-1
Main Slab | REINFORCEMENT_UNIT | 526875 | -6" | 0" | 1-7/G-A | A5 | Tekla Assembly - Cast unit type: Precast; Cast unit rebar weight: 0 kg

# IfcMechanicalFastener: Bolt assembly (1721)
In: Undefined
Name | NominalDiameter (mm) | NominalLength (mm) | Material | Washer count | Washer diameter (mm) | Washer type | Washer name | Nut count | Nut type | Nut name | Slotted hole y (mm) | Slotted hole x (mm) | Bolt hole diameter (mm) | Location | Bolt count | Bolt size (mm) | Bolt length (mm) | Bolt standard | Bolt Name
5 x Bolt assembly | 12.7 | 38.1 | Undefined | 8 | 12.7 | A307 | BL-2 | 4 | A307 | BL-3 | 0 | 0 | 14.3 | Site | 4 | 12.7 | 38.1 | A307 | BL
18 x Bolt assembly | 12.7 | 38.1 | Undefined | 4 | 12.7 | A307 | BL-2 | 2 | A307 | BL-3 | 0 | 11.9 | 14.3 | Site | 2 | 12.7 | 38.1 | A307 | BL
3 x Bolt assembly | 12.7 | 38.1 | Undefined | 0 | 12.7 | A307 | BL-2 | 0 | A307 | BL-3 | 11.9 | 0 | 14.3 | Site | 2 | 14.3 | 38.1 | A307 | BL
328 x Bolt assembly | 12.7 | 38.1 | Undefined | 4 | 12.7 | A307 | BL-2 | 2 | A307 | BL-3 | 0 | 0 | 14.3 | Site | 2 | 14.3 | 38.1 | A307 | BL
2 x Bolt assembly | 12.7 | 38.1 | Undefined | 8 | 12.7 | A307 | BL-2 | 4 | A307 | BL-3 | 17.5 | 0 | 14.3 | Site | 4 | 12.7 | 38.1 | A307 | BL
58 x Bolt assembly | 19.05 | 31.75 | Undefined | 0 | 19 | PLAIN | BH-9 | 0 | HEAVY_HEX | BH-8 | 7.9 | 38.1 | 19 | Workshop | 1 | 19 | 31.8 | A325N | BOLT 3/4"DIA A325 1"1/4
4 x Bolt assembly | 12.7 | 38.1 | Undefined | 0 | 12.7 | A307 | BL-2 | 0 | A307 | BL-3 | 0 | 0 | 14.3 | Site | 2 | 14.3 | 38.1 | A307 | BL
64 x Bolt assembly | 12.7 | 38.1 | Undefined | 2 | 12.7 | A307 | BL-2 | 2 | A307 | BL-3 | 0 | 0 | 14.3 | Site | 2 | 12.7 | 38.1 | A307 | BL
2 x Bolt assembly | 19.05 | 9.525 | Undefined | 2 | 19 | PLAIN | BH-9 | 2 | HEAVY_HEX | BH-8 | 0 | 0 | 22.2 | Site | 2 | 22.2 | 9.5 | A325T | BH
13 x Bolt assembly | 12.7 | 25.4 | Undefined | 2 | 12.7 | A307 | BL-2 | 2 | A307 | BL-3 | 0 | 0 | 14.3 | Site | 2 | 12.7 | 25.4 | FHB | BL
39 x Bolt assembly | 12.7 | 38.1 | Undefined | 4 | 12.7 | A307 | BL-2 | 2 | A307 | BL-3 | 0 | 0 | 14.3 | Site | 2 | 12.7 | 38.1 | A307 | BL
4 x Bolt assembly | 12.7 | 38.1 | Undefined | 0 | 12.7 | A307 | BL-2 | 2 | A307 | BL-3 | 0 | 0 | 14.3 | Site | 2 | 14.3 | 38.1 | A307 | BL
276 x Bolt assembly | 12.7 | 38.1 | Undefined | 2 | 12.7 | A307 | BL-2 | 1 | A307 | BL-3 | 0 | 0 | 14.3 | Site | 1 | 12.7 | 38.1 | A307 | BL
198 x Bolt assembly | 12.7 | 38.1 | 7990 | 1 | 12.7 |  |  | 1 |  |  | 0 | 0 | 14.3 | Site | 1 | 14.3 | 38.1 | 7990
148 x Bolt assembly | 12.7 | 38.1 | Undefined | 1 | 12.7 | A307 | BL-2 | 1 | A307 | BL-3 | 0 | 0 | 14.3 | Site | 1 | 12.7 | 38.1 | A307 | BL
10 x Bolt assembly | 12.7 | 38.1 | 7990 | 2 | 12.7 |  |  | 2 |  |  | 0 | 0 | 14.3 | Site | 2 | 14.3 | 38.1 | 7990
248 x Bolt assembly | 12.7 | 38.1 | Undefined | 0 | 12.7 | A307 | BL-2 | 2 | A307 | BL-3 | 0 | 0 | 14.3 | Site | 2 | 12.7 | 38.1 | A307 | BL
6 x Bolt assembly | 12.7 | 50.8 | Undefined | 1 | 12.7 | PLAIN | BH-4 | 1 | HEAVY_HEX | BH-3 | 0 | 0 | 14.3 | Site | 1 | 14.3 | 50.8 | A325T | BH
16 x Bolt assembly | 25.4 | 31.75 | Undefined | 0 | 25.4 | PLAIN | BH-23 | 0 | HEAVY_HEX | BH-22 | 9.5 | 47.6 | 25.4 | Workshop | 1 | 25.4 | 31.8 | A325N | BOLT 1"DIA A325 1"1/4
5 x Bolt assembly | 19.05 | 69.85 | Undefined | 2 | 19 | PLAIN | BH-9 | 1 | HEAVY_HEX | BH-8 | 0 | 0 | 20.6 | Site | 1 | 19 | 69.8 | A325T | BH
Bolt assembly | 19.05 | 69.85 | Undefined | 1 | 19 | PLAIN | BH-9 | 1 | HEAVY_HEX | BH-8 | 0 | 0 | 20.6 | Site | 1 | 19 | 69.8 | A325T | BH
14 x Bolt assembly | 12.7 | 38.1 | Undefined | 0 | 12.7 | A307 | BL-2 | 4 | A307 | BL-3 | 0 | 0 | 14.3 | Site | 4 | 12.7 | 38.1 | A307 | BL
17 x Bolt assembly | 12.7 | 50.8 | Undefined | 1 | 12.7 | PLAIN | BH-4 | 1 | HEAVY_HEX | BH-3 | 0 | 0 | 14.3 | Site | 1 | 12.7 | 50.8 | A325T | BH
11 x Bolt assembly | 12.7 | 50.8 | Undefined | 2 | 12.7 | PLAIN | BH-4 | 1 | HEAVY_HEX | BH-3 | 0 | 0 | 14.3 | Site | 1 | 12.7 | 50.8 | A325T | BH
74 x Bolt assembly | 12.7 | 50.8 | Undefined | 2 | 12.7 | PLAIN | BH-4 | 2 | HEAVY_HEX | BH-3 | 0 | 0 | 14.3 | Site | 2 | 12.7 | 50.8 | A325T | BH
18 x Bolt assembly | 12.7 | 50.8 | Undefined | 0 | 12.7 | PLAIN | BH-4 | 2 | HEAVY_HEX | BH-3 | 0 | 0 | 14.3 | Site | 2 | 14.3 | 50.8 | A325T | BH
18 x Bolt assembly | 12.7 | 50.8 | Undefined | 4 | 12.7 | PLAIN | BH-4 | 2 | HEAVY_HEX | BH-3 | 0 | 0 | 14.3 | Site | 2 | 12.7 | 50.8 | A325T | BH
5 x Bolt assembly | 12.7 | 38.1 | Undefined | 0 | 12.7 | A307 | BL-2 | 0 | A307 | BL-3 | 0 | 11.1 | 14.3 | Site | 2 | 14.3 | 38.1 | A307 | BL
5 x Bolt assembly | 12.7 | 38.1 | Undefined | 4 | 12.7 | A307 | BL-2 | 2 | A307 | BL-3 | 0 | 11.1 | 14.3 | Site | 2 | 12.7 | 38.1 | A307 | BL
20 x Bolt assembly | 19.05 | 69.85 | Undefined | 2 | 19 | PLAIN | BH-9 | 2 | HEAVY_HEX | BH-8 | 0 | 0 | 20.6 | Site | 2 | 19 | 69.8 | A325T | BH
2 x Bolt assembly | 12.7 | 38.1 | Undefined | 0 | 12.7 | A307 | BL-2 | 0 | A307 | BL-3 | 11.1 | 0 | 14.3 | Site | 4 | 14.3 | 38.1 | A307 | BL
2 x Bolt assembly | 12.7 | 38.1 | Undefined | 0 | 12.7 | A307 | BL-2 | 0 | A307 | BL-3 | 11.1 | 0 | 14.3 | Site | 2 | 14.3 | 38.1 | A307 | BL
3 x Bolt assembly | 12.7 | 50.8 | Undefined | 4 | 12.7 | PLAIN | BH-4 | 4 | HEAVY_HEX | BH-3 | 0 | 0 | 14.3 | Site | 4 | 12.7 | 50.8 | A325T | BH
22 x Bolt assembly | 19.05 | 69.85 | Undefined | 4 | 19 | PLAIN | BH-9 | 4 | HEAVY_HEX | BH-8 | 0 | 0 | 20.6 | Site | 4 | 19 | 69.8 | A325T | BH
48 x Bolt assembly | 19.05 | 69.85 | Undefined | 6 | 19 | PLAIN | BH-9 | 6 | HEAVY_HEX | BH-8 | 0 | 0 | 20.6 | Site | 6 | 19 | 69.8 | A325T | BH
14 x Bolt assembly | 31.75 | 15.875 | 7990 | 4 | 31.8 |  |  | 4 |  |  | 0 | 0 | 36.5 | Site | 4 | 36.5 | 15.9 | 7990

# IfcMember: 1_HEAVY_HEX_NUT (16)
In: Undefined
Description: 1_HEAVY_HEX_NUT; Material: STEEL/55
Tekla Common - Phase: 1; Class: 6
Tekla Quantity - Weight: 0.1 kg; Volume: 0 m3; Gross footprint area: 0 m2; Area per tons: 48 m2; Net surface area: 0 m2; Height: 41.2 mm; Width: 47.6 mm
Pset_MemberCommon - LoadBearing: yes; Reference: BH-57
Name | Bottom elevation | Top elevation | Length (mm)
8 x 1 H HEX NUT A563 | 4"5/16 | 6"1/4 | 19.1
4 x 1 H HEX NUT A563 | 18'-10"13/16 | 19'-0"3/4 | 19.1
1 H HEX NUT A563 | 18'-11" | 19'-0"15/16 | 19
3 x 1 H HEX NUT A563 | 18'-11" | 19'-0"15/16 | 19.1

# IfcMember: 1_WASHER (16)
In: Undefined
Description: 1_WASHER; Material: STEEL/55
Tekla Common - Phase: 1; Class: 6
Tekla Quantity - Weight: 0.1 kg; Volume: 0 m3; Gross footprint area: 0 m2; Area per tons: 77 m2; Net surface area: 0 m2; Height: 49.5 mm; Width: 50.8 mm; Length: 4.8 mm
Pset_MemberCommon - LoadBearing: yes; Reference: BH-58
Name | Bottom elevation | Top elevation
8 x 1 WASHER F844 | 4"11/16 | 6"7/16
4 x 1 WASHER F844 | 18'-10"5/8 | 19'-0"3/8
2 x 1 WASHER F844 | 18'-10"7/8 | 19'-0"9/16
2 x 1 WASHER F844 | 18'-10"13/16 | 19'-0"9/16

# IfcMember: FB- (140)
In: Undefined
Description: FB-; Material: STEEL/55
Tekla Common - Finish: GZ; Phase: 1; Class: 2
Tekla Quantity - Volume: 0 m3; Gross footprint area: 0 m2; Area per tons: 163 m2; Height: 50.8 mm; Width: 50.8 mm
Pset_MemberCommon - LoadBearing: yes
Name | Bottom elevation | Top elevation | Weight (kg) | Net surface area (m2) | Length (mm) | Reference
8 x 2X2 FLANGE BRACE X 48 | 19'-7"3/8 | 22'-2" | 1.7 | 0.3 | 1389.3 | FB-48
12 x 2X2 FLANGE BRACE X 48 | 19'-7"3/8 | 22'-2" | 1.2 | 0.2 | 1067.8 | FB-48
12 x 2X2 FLANGE BRACE X 48 | 20'-5"5/16 | 23'-0" | 1.2 | 0.2 | 1067.8 | FB-48
8 x 2X2 FLANGE BRACE X 48 | 20'-5"3/8 | 22'-11"15/16 | 1.7 | 0.3 | 1389.3 | FB-48
12 x 2X2 FLANGE BRACE X 48 | 21'-3"1/4 | 23'-9"15/16 | 1.2 | 0.2 | 1067.8 | FB-48
8 x 2X2 FLANGE BRACE X 48 | 21'-3"5/16 | 23'-9"7/8 | 1.7 | 0.3 | 1389.3 | FB-48
12 x 2X2 FLANGE BRACE X 48 | 21'-8"1/4 | 24'-2"15/16 | 1.2 | 0.2 | 1067.8 | FB-48
8 x 2X2 FLANGE BRACE X 48 | 21'-8"5/16 | 24'-2"7/8 | 1.7 | 0.3 | 1389.3 | FB-48
4 x 2X2 FLANGE BRACE X 48 | 21'-4"3/8 | 24'-2"7/8 | 1.2 | 0.2 | 1022.9 | FB-48
4 x 2X2 FLANGE BRACE X 48 | 20'-11"3/8 | 23'-9"15/16 | 1.2 | 0.2 | 1022.9 | FB-48
4 x 2X2 FLANGE BRACE X 48 | 20'-1"7/16 | 22'-11"15/16 | 1.2 | 0.2 | 1022.9 | FB-48
4 x 2X2 FLANGE BRACE X 48 | 19'-3"7/16 | 22'-2" | 1.2 | 0.2 | 1022.9 | FB-48
2 x 2X2 FLANGE BRACE X 48 | 18'-5" | 21'-4" | 1.2 | 0.2 | 1032.6 | FB-48
2 x 2X2 FLANGE BRACE X 48 | 18'-5" | 21'-4" | 1.2 | 0.2 | 1032.4 | FB-48
6 x 2X2 FLANGE BRACE X 48 | 18'-7"5/8 | 21'-4"1/16 | 1.4 | 0.2 | 1098.5 | FB-48
4 x 2X2 FLANGE BRACE X 48 | 18'-7"11/16 | 21'-4" | 1.7 | 0.3 | 1412.6 | FB-48
6 x 2X2 FLANGE BRACE X 60 | 17'-2"9/16 | 20'-6"9/16 | 1.6 | 0.3 | 1245.8 | FB-60
4 x 2X2 FLANGE BRACE X 60 | 17'-2"9/16 | 20'-6"9/16 | 1.9 | 0.3 | 1528.9 | FB-60
6 x 2X2 FLANGE BRACE X 48 | 18'-7"11/16 | 21'-4"1/16 | 1.4 | 0.2 | 1097.9 | FB-48
4 x 2X2 FLANGE BRACE X 48 | 18'-7"3/4 | 21'-4" | 1.7 | 0.3 | 1412.1 | FB-48
6 x 2X2 FLANGE BRACE X 60 | 17'-2"13/16 | 20'-6"9/16 | 1.4 | 0.3 | 1241.7 | FB-60
4 x 2X2 FLANGE BRACE X 60 | 17'-2"3/4 | 20'-6"9/16 | 1.9 | 0.3 | 1525.6 | FB-60

# IfcMember: HSS4X4X1/4 (2)
In: Undefined
Description: HSS4X4X1/4; Material: STEEL/55
Tekla Common - Finish: GP; Bottom elevation: 13'-10"7/8; Phase: 1; Class: 1
Tekla Quantity - Volume: 0 m3; Gross footprint area: 0 m2; Area per tons: 22.7 m2; Net surface area: 2.9 m2; Height: 101.6 mm; Width: 101.6 mm
Pset_MemberCommon - LoadBearing: yes
Name | Top elevation | Weight (kg) | Length (mm) | Reference
PIPE | 22'-4" | 122.5 | 7178.9 | TF-1
PIPE | 22'-4"7/16 | 122.6 | 7182.7 | TF-3

# IfcMember: L3X3X1/4 (4)
In: Undefined
Description: L3X3X1/4; Material: STEEL/55
Tekla Common - Finish: GP; Top elevation: 20'-6"3/4; Phase: 1; Class: 2
Tekla Quantity - Weight: 9.5 kg; Volume: 0 m3; Gross footprint area: 0 m2; Area per tons: 42 m2; Net surface area: 0.3 m2; Height: 76.2 mm; Width: 76.2 mm
Pset_MemberCommon - LoadBearing: yes
Name | Bottom elevation | Length (mm) | Reference
2 x MISC STRUCTURAL ANGLE | 17'-1"9/16 | 1307.8 | FA-2
2 x MISC STRUCTURAL ANGLE | 17'-1"11/16 | 1305.8 | FA-1

# IfcMember: RB1" (8)
In: Undefined
Description: RB1"; Material: STEEL/55
Tekla Common - Bottom elevation: 3"1/4; Phase: 1; Class: 14
Tekla Quantity - Weight: 36.9 kg; Volume: 0 m3; Gross footprint area: 0 m2; Area per tons: 20.8 m2; Net surface area: 0.8 m2; Height: 25.4 mm; Width: 25.4 mm
Pset_MemberCommon - LoadBearing: yes; Reference: r8_1
Name | Top elevation | Length (mm)
4 x ROD BRACE - 1 | 19'-1"13/16 | 9702.5
4 x ROD BRACE - 1 | 19'-2" | 9702.6

# IfcPlate: PL1 3/4"X1 5/8" (64)
In: Undefined
Description: PL1 3/4"X1 5/8"; Material: STEEL/A992
Tekla Common - Phase: 1; Class: 3
Tekla Quantity - Weight: 0.9 kg; Volume: 0 m3; Gross footprint area: 0 m2; Area per tons: 16.1 m2; Net surface area: 0 m2; Height: 41.1 mm; Width: 44.5 mm; Length: 76 mm
Pset_PlateCommon - LoadBearing: yes
Name | Bottom elevation | Top elevation | Reference
8 x 1 & 1 1/4 HILL WASHER | 5"3/16 | 8"3/16 | BR-60
7 x 3/4 HILL WASHER | 20'-10"13/16 | 21'-0"13/16 | BR-75
4 x 3/4 HILL WASHER | 20'-9"15/16 | 20'-11"15/16 | BR-75
4 x 3/4 HILL WASHER | 20'-9"15/16 | 20'-11"7/8 | BR-75
4 x 1 & 1 1/4 HILL WASHER | 18'-8"3/4 | 18'-11"3/4 | BR-60
4 x 1 & 1 1/4 HILL WASHER | 18'-9"1/16 | 19'-0"1/16 | BR-60
8 x 3/4 HILL WASHER | 22'-6"3/8 | 22'-8"3/8 | BR-75
8 x 3/4 HILL WASHER | 23'-4"5/8 | 23'-6"5/8 | BR-75
8 x 3/4 HILL WASHER | 22'-5"3/4 | 22'-7"3/4 | BR-75
3/4 HILL WASHER | 20'-11" | 21'-1" | BR-75
4 x 3/4 HILL WASHER | 19'-1"7/8 | 19'-3"7/8 | BR-75
4 x 3/4 HILL WASHER | 19'-2"3/16 | 19'-4"3/16 | BR-75

# IfcSlab: 6"X1260", Main Slab
In: Undefined
Description: 6"X1260"; PredefinedType: FLOOR; Material: CONCRETE/3000
Tekla Common - Bottom elevation: -6"; Top elevation: 0"; Phase: 1; Class: 1
Tekla Quantity - Weight: 526875 kg; Volume: 219.3 m3; Gross footprint area: 1438.8 m2; Area per tons: 5.5 m2; Net surface area: 2901.1 m2; Height: 32004 mm; Width: 152.4 mm; Length: 44958 mm
Pset_SlabCommon - LoadBearing: yes; Reference: P5
